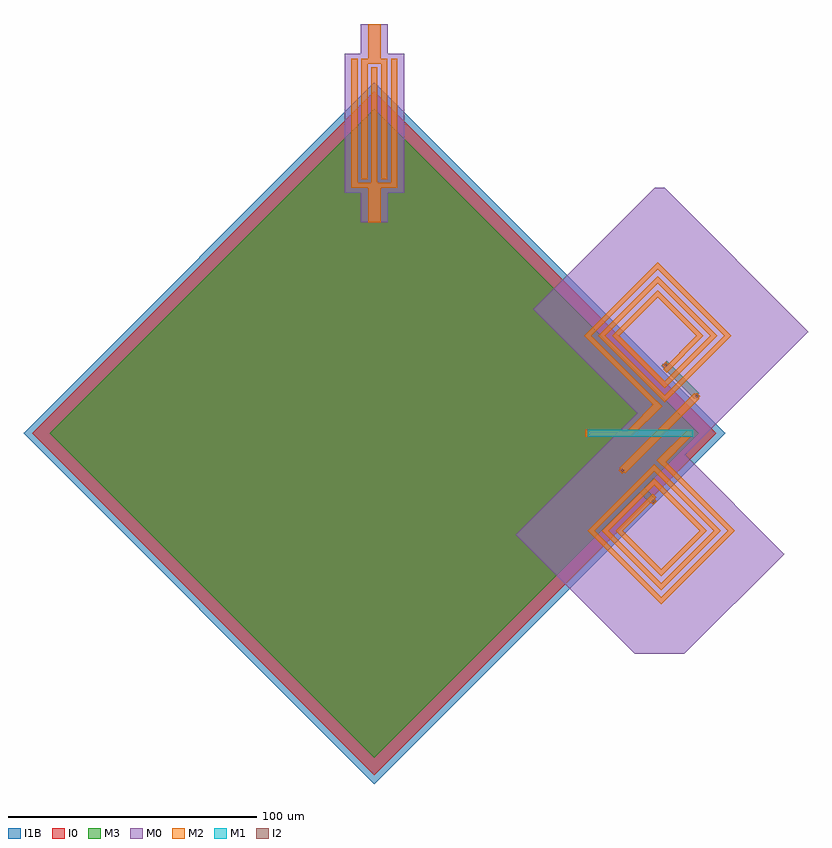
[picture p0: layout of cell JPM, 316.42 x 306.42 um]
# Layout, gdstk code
from math import pi, radians
import gdstk
lib = gdstk.Library(unit=1e-6, precision=1e-09)
def R(c, l, rs):  # rectangles x0, y0, x1, y1
    for r in rs: c.add(gdstk.rectangle(r[:2], r[2:], *l))
def P(c, l, *ps):  # polygons
    for p in ps: c.add(gdstk.Polygon(p, *l))
M1 = (1, 0)
I1B = (3, 0)
M2 = (6, 0)
I2 = (8, 0)
M3 = (10, 0)
M0 = (30, 0)
I0 = (31, 0)

shuntcapacitor = lib.new_cell('ShuntCapacitor')
R(shuntcapacitor, I1B, [(-100,-100,100,100)])
R(shuntcapacitor, M3, [(-92.5,-92.5,92.5,92.5)])
R(shuntcapacitor, I0, [(-97.5,-97.5,97.5,97.5)])

rocap = lib.new_cell('ROCap')
P(rocap, M2, [(-26,-5.25),(-26,-2.5),(-40,-2.5),(-40,2.5),(-26,2.5),(-26,5.25),(22.5,5.25),(22.5,2.75),(-24,2.75),(-24,-2.75),(22.5,-2.75),(22.5,-5.25)],
  [(-26,-9.25),(-26,-6.75),(24,-6.75),(24,-1.25),(-22.5,-1.25),(-22.5,1.25),(24,1.25),(24,6.75),(-26,6.75),(-26,9.25),(26,9.25),(26,2.5),(40,2.5),(40,-2.5),(26,-2.5),(26,-9.25)])
P(rocap, M0, [(-28,-12),(-28,-5.5),(-40,-5.5),(-40,5.5),(-28,5.5),(-28,12),(28,12),(28,5.5),(40,5.5),(40,-5.5),(28,-5.5),(28,-12)])

squarespiral = lib.new_cell('SquareSpiral')
squarespiral.add(gdstk.FlexPath([(-9,12),(11,12),(11,-12),(-13,-12),(-13,16),(15,16),(15,-16),(-17,-16),(-17,20),(19,20),(19,-20),(-21,-20),(-21,21)], 2, ends="flush", simple_path=True, layer=6, datatype=0))  # M2

via_m3_m2_1 = lib.new_cell('Via$M3-M2$1')
R(via_m3_m2_1, M2, [(-1,-1,1,1)])
R(via_m3_m2_1, I2, [(-0.5,-0.5,0.5,0.5)])
R(via_m3_m2_1, M3, [(-1,-1,1,1)])

via_m2_m1_3 = lib.new_cell('Via$M2-M1$3')
R(via_m2_m1_3, M1, [(-1.5,-1.5,1.5,1.5)])
R(via_m2_m1_3, I1B, [(-1,-1,1,1)])
R(via_m2_m1_3, M2, [(-1.5,-1.5,1.5,1.5)])

jpm = lib.new_cell('JPM')
P(jpm, M0, [(47,-89),(-1,-41),(48,8),(6,50),(55,99),(59,99),(117,41),(67.25,-8.75),(107.25,-48.75),(67,-89)])
jpm.add(gdstk.FlexPath([(69,0),(57,-12)], 3, ends="flush", simple_path=True, layer=6, datatype=0))  # M2
jpm.add(gdstk.FlexPath([(57,12),(45,0),(37,0)], 3, ends="flush", simple_path=True, layer=6, datatype=0))  # M2
jpm.add(gdstk.FlexPath([(72,15),(42,-15)], 3, ends="flush", simple_path=True, layer=6, datatype=0))  # M2
jpm.add(gdstk.FlexPath([(27,0),(43,0)], 3, ends="flush", simple_path=True, layer=6, datatype=0))  # M2
jpm.add(gdstk.FlexPath([(68.5,0),(28,0)], 3, ends="flush", simple_path=True, layer=1, datatype=0))  # M1
jpm.add(gdstk.FlexPath([(72,15),(58.75,28.25)], 3, ends="flush", simple_path=True, layer=10, datatype=0))  # M3
jpm.add(gdstk.FlexPath([(42,-15),(54.222,-27.222)], 3, ends="flush", simple_path=True, layer=10, datatype=0))  # M3
jpm.add(gdstk.Reference(shuntcapacitor, (-58,0), rotation=radians(45)))
jpm.add(gdstk.Reference(rocap, (-58,125), rotation=3*pi/2))
jpm.add(gdstk.Reference(squarespiral, (57,-40), rotation=radians(225), x_reflection=True))
jpm.add(gdstk.Reference(squarespiral, (57,40), rotation=radians(45), x_reflection=True))
jpm.add(gdstk.Reference(via_m3_m2_1, (59.5,27.5), rotation=radians(45)))
jpm.add(gdstk.Reference(via_m3_m2_1, (54.5,-27.5), rotation=radians(45)))
jpm.add(gdstk.Reference(via_m3_m2_1, (42,-15), rotation=radians(45)))
jpm.add(gdstk.Reference(via_m3_m2_1, (72,15), rotation=radians(45)))
jpm.add(gdstk.Reference(via_m2_m1_3, (69,0)))

lib.write_gds('JPM.gds')
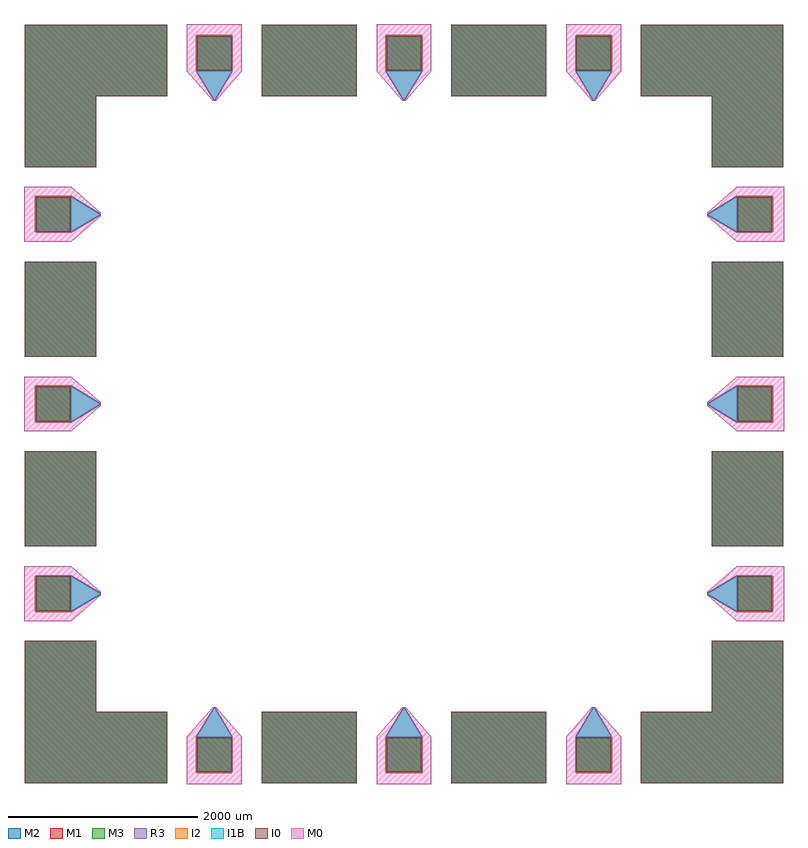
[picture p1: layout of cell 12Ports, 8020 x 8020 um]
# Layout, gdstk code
from math import pi, radians
import gdstk
lib = gdstk.Library(unit=1e-6, precision=1e-09)
def R(c, l, rs):  # rectangles x0, y0, x1, y1
    for r in rs: c.add(gdstk.rectangle(r[:2], r[2:], *l))
def P(c, l, *ps):  # polygons
    for p in ps: c.add(gdstk.Polygon(p, *l))
M1 = (1, 0)
I1B = (3, 0)
M2 = (6, 0)
I2 = (8, 0)
M3 = (10, 0)
R3 = (11, 0)
M0 = (30, 0)
I0 = (31, 0)

rfpad = lib.new_cell('rfPad')
R(rfpad, M1, [(-190,310,190,690)])
R(rfpad, I1B, [(-182.5,317.5,182.5,682.5)])
R(rfpad, M2, [(-190,310,190,690)])
P(rfpad, M2, [(-5,0),(-190,310),(190,310),(5,0)])
R(rfpad, I2, [(-185,315,185,685)])
R(rfpad, M3, [(-190,310,190,690)])
R(rfpad, R3, [(-187.5,312.5,187.5,687.5)])
R(rfpad, M0, [(-290,310,-190,690), (190,310,290,690), (-290,690,290,810)])
P(rfpad, M0, [(-17,0),(-290,310),(-190,310),(-5,0)],
  [(5,0),(190,310),(290,310),(17,0)])
R(rfpad, I0, [(-180,320,180,680)])

cornergroundpad = lib.new_cell('CornerGroundPad')
P(cornergroundpad, M1, [(-750,-750),(-750,750),(750,750),(750,0),(0,0),(0,-750)])
P(cornergroundpad, I1B, [(-750,-750),(-750,750),(750,750),(750,0),(0,0),(0,-750)])
P(cornergroundpad, M2, [(-750,-750),(-750,750),(750,750),(750,0),(0,0),(0,-750)])
P(cornergroundpad, I2, [(-750,-750),(-750,750),(750,750),(750,0),(0,0),(0,-750)])
P(cornergroundpad, M3, [(-750,-750),(-750,750),(750,750),(750,0),(0,0),(0,-750)])
P(cornergroundpad, R3, [(-750,-750),(-750,750),(750,750),(750,0),(0,0),(0,-750)])
P(cornergroundpad, I0, [(-750,-750),(-750,750),(750,750),(750,0),(0,0),(0,-750)])

groundpad = lib.new_cell('GroundPad')
R(groundpad, M1, [(-375,-500,375,500)])
R(groundpad, I1B, [(-375,-500,375,500)])
R(groundpad, M2, [(-375,-500,375,500)])
R(groundpad, I2, [(-375,-500,375,500)])
R(groundpad, M3, [(-375,-500,375,500)])
R(groundpad, R3, [(-375,-500,375,500)])
R(groundpad, I0, [(-375,-500,375,500)])

c_12ports = lib.new_cell('12Ports')
c_12ports.add(gdstk.Reference(rfpad, (-3200,0), rotation=pi/2))
c_12ports.add(gdstk.Reference(rfpad, (-3200,-2000), rotation=pi/2))
c_12ports.add(gdstk.Reference(rfpad, (-2000,-3200), rotation=pi))
c_12ports.add(gdstk.Reference(rfpad, (0,-3200), rotation=pi))
c_12ports.add(gdstk.Reference(rfpad, (2000,-3200), rotation=pi))
c_12ports.add(gdstk.Reference(rfpad, (3200,-2000), rotation=3*pi/2))
c_12ports.add(gdstk.Reference(rfpad, (3200,0), rotation=3*pi/2))
c_12ports.add(gdstk.Reference(rfpad, (3200,2000), rotation=3*pi/2))
c_12ports.add(gdstk.Reference(rfpad, (2000,3200)))
c_12ports.add(gdstk.Reference(rfpad, (-3200,2000), rotation=pi/2))
c_12ports.add(gdstk.Reference(rfpad, (0,3200)))
c_12ports.add(gdstk.Reference(rfpad, (-2000,3200)))
c_12ports.add(gdstk.Reference(cornergroundpad, (-3250,3250)))
c_12ports.add(gdstk.Reference(cornergroundpad, (3250,3250), rotation=3*pi/2))
c_12ports.add(gdstk.Reference(cornergroundpad, (-3250,-3250), rotation=pi/2))
c_12ports.add(gdstk.Reference(cornergroundpad, (3250,-3250), rotation=pi))
c_12ports.add(gdstk.Reference(groundpad, (-3625,1000)))
c_12ports.add(gdstk.Reference(groundpad, (-3625,-1000), rotation=pi))
c_12ports.add(gdstk.Reference(groundpad, (3625,1000), rotation=pi))
c_12ports.add(gdstk.Reference(groundpad, (3625,-1000), rotation=pi))
c_12ports.add(gdstk.Reference(groundpad, (-1000,-3625), rotation=3*pi/2))
c_12ports.add(gdstk.Reference(groundpad, (1000,-3625), rotation=3*pi/2))
c_12ports.add(gdstk.Reference(groundpad, (-1000,3625), rotation=3*pi/2))
c_12ports.add(gdstk.Reference(groundpad, (1000,3625), rotation=3*pi/2))

lib.write_gds('12Ports.gds')
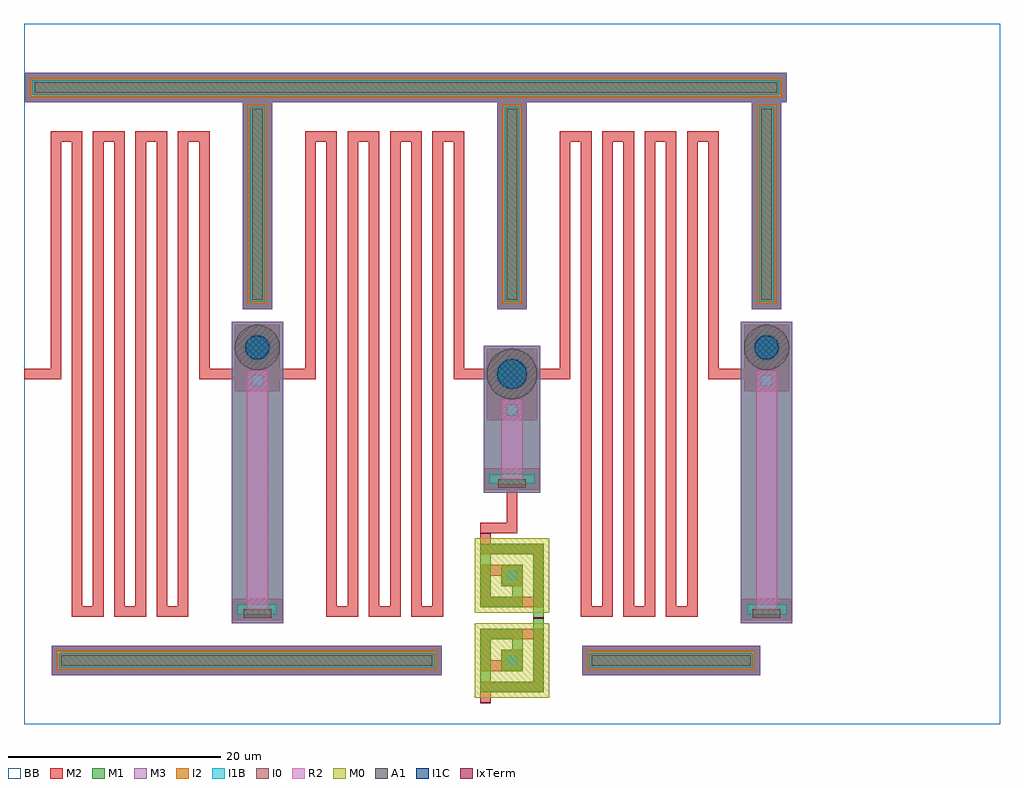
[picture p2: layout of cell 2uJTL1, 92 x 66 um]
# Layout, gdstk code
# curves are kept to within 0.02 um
from math import pi, radians
import gdstk
lib = gdstk.Library(unit=1e-6, precision=1e-09)
def R(c, l, rs):  # rectangles x0, y0, x1, y1
    for r in rs: c.add(gdstk.rectangle(r[:2], r[2:], *l))
def P(c, l, *ps):  # polygons
    for p in ps: c.add(gdstk.Polygon(p, *l))
M1 = (1, 0)
BB = (1, 3)
I1B = (3, 0)
I1C = (4, 0)
A1 = (5, 0)
M2 = (6, 0)
I2 = (8, 0)
R2 = (9, 0)
M3 = (10, 0)
M0 = (30, 0)
I0 = (31, 0)
IxTerm = (63, 0)

via_m3_m0_9 = lib.new_cell('Via$M3-M0$9')
via_m3_m0_9.add(gdstk.FlexPath([(-9.2,0),(9.2,0)], 1.399, ends="flush", simple_path=True, layer=3, datatype=0))  # I1B
via_m3_m0_9.add(gdstk.FlexPath([(-9.899,0),(9.899,0)], 2.799, ends="flush", simple_path=True, layer=6, datatype=0))  # M2
via_m3_m0_9.add(gdstk.FlexPath([(-9.899,0),(9.899,0)], 2.799, ends="flush", simple_path=True, layer=1, datatype=0))  # M1
via_m3_m0_9.add(gdstk.FlexPath([(-9.899,0),(9.899,0)], 2.799, ends="flush", simple_path=True, layer=10, datatype=0))  # M3
via_m3_m0_9.add(gdstk.FlexPath([(-9.399,0),(9.399,0)], 1.8, ends="flush", simple_path=True, layer=8, datatype=0))  # I2
via_m3_m0_9.add(gdstk.FlexPath([(-9,0),(9,0)], 1, ends="flush", simple_path=True, layer=31, datatype=0))  # I0

jj_64 = lib.new_cell('JJ$64')
R(jj_64, M1, [(-2.429,-25.993,2.429,2.429)])
R(jj_64, I1B, [(-1.879,-25.193,1.879,-24.193), (-0.5,-3.63,0.5,-2.63)])
P(jj_64, I1B, [(0,-1.185),(-0.231,-1.162),(-0.453,-1.095),(-0.658,-0.985),(-0.838,-0.838),(-0.985,-0.658),(-1.095,-0.453),(-1.162,-0.231),(-1.185,0),(-1.162,0.231),(-1.095,0.453),(-0.985,0.658),(-0.838,0.838),(-0.658,0.985),(-0.453,1.095),(-0.231,1.162),(0,1.185),(0.231,1.162),(0.453,1.095),(0.658,0.985),(0.838,0.838),(0.985,0.658),(1.095,0.453),(1.162,0.231),(1.185,0),(1.162,-0.231),(1.095,-0.453),(0.985,-0.658),(0.838,-0.838),(0.658,-0.985),(0.453,-1.095),(0.231,-1.162)])
P(jj_64, I1C, [(0,-1.128),(-0.22,-1.107),(-0.432,-1.042),(-0.627,-0.938),(-0.798,-0.798),(-0.938,-0.627),(-1.042,-0.432),(-1.107,-0.22),(-1.128,0),(-1.107,0.22),(-1.042,0.432),(-0.938,0.627),(-0.798,0.798),(-0.627,0.938),(-0.432,1.042),(-0.22,1.107),(0,1.128),(0.22,1.107),(0.432,1.042),(0.627,0.938),(0.798,0.798),(0.938,0.627),(1.042,0.432),(1.107,0.22),(1.128,0),(1.107,-0.22),(1.042,-0.432),(0.938,-0.627),(0.798,-0.798),(0.627,-0.938),(0.432,-1.042),(0.22,-1.107)])
P(jj_64, A1, [(0,-2.13),(-0.416,-2.089),(-0.815,-1.968),(-1.183,-1.771),(-1.506,-1.506),(-1.771,-1.183),(-1.968,-0.815),(-2.089,-0.416),(-2.13,0),(-2.089,0.416),(-1.968,0.815),(-1.771,1.183),(-1.506,1.506),(-1.183,1.771),(-0.815,1.968),(-0.416,2.089),(0,2.13),(0.416,2.089),(0.815,1.968),(1.183,1.771),(1.506,1.506),(1.771,1.183),(1.968,0.815),(2.089,0.416),(2.13,0),(2.089,-0.416),(1.968,-0.815),(1.771,-1.183),(1.506,-1.506),(1.183,-1.771),(0.815,-1.968),(0.416,-2.089)])
R(jj_64, M2, [(-2.38,-25.693,2.38,-23.693), (-2.13,-4.13,2.13,-2.13), (-2.13,-2.13,2.13,2.13)])
R(jj_64, I2, [(-1.879,-25.193,1.879,-24.193)])
R(jj_64, M3, [(-2.429,-25.993,2.429,2.429), (-2.38,-25.693,2.38,-23.693)])
R(jj_64, I0, [(-1.3,-25.493,1.3,-24.693)])
jj_64.add(gdstk.FlexPath([(0,-2.13),(0,-24.693)], 2, ends="flush", simple_path=True, layer=9, datatype=0))  # R2

jj_69 = lib.new_cell('JJ$69')
R(jj_69, M1, [(-2.679,-11.201,2.679,2.679)])
R(jj_69, I1B, [(-2.13,-10.401,2.13,-9.401), (-0.5,-3.88,0.5,-2.88)])
P(jj_69, I1B, [(0,-1.451),(-0.283,-1.423),(-0.555,-1.341),(-0.806,-1.207),(-1.026,-1.026),(-1.207,-0.806),(-1.341,-0.555),(-1.423,-0.283),(-1.451,0),(-1.423,0.283),(-1.341,0.555),(-1.207,0.806),(-1.026,1.026),(-0.806,1.207),(-0.555,1.341),(-0.283,1.423),(0,1.451),(0.283,1.423),(0.555,1.341),(0.806,1.207),(1.026,1.026),(1.207,0.806),(1.341,0.555),(1.423,0.283),(1.451,0),(1.423,-0.283),(1.341,-0.555),(1.207,-0.806),(1.026,-1.026),(0.806,-1.207),(0.555,-1.341),(0.283,-1.423)])
P(jj_69, I1C, [(0,-1.382),(-0.27,-1.355),(-0.529,-1.277),(-0.768,-1.149),(-0.977,-0.977),(-1.149,-0.768),(-1.277,-0.529),(-1.355,-0.27),(-1.382,0),(-1.355,0.27),(-1.277,0.529),(-1.149,0.768),(-0.977,0.977),(-0.768,1.149),(-0.529,1.277),(-0.27,1.355),(0,1.382),(0.27,1.355),(0.529,1.277),(0.768,1.149),(0.977,0.977),(1.149,0.768),(1.277,0.529),(1.355,0.27),(1.382,0),(1.355,-0.27),(1.277,-0.529),(1.149,-0.768),(0.977,-0.977),(0.768,-1.149),(0.529,-1.277),(0.27,-1.355)])
P(jj_69, A1, [(0,-2.38),(-0.464,-2.334),(-0.911,-2.199),(-1.322,-1.979),(-1.683,-1.683),(-1.979,-1.322),(-2.199,-0.911),(-2.334,-0.464),(-2.38,0),(-2.334,0.464),(-2.199,0.911),(-1.979,1.322),(-1.683,1.683),(-1.322,1.979),(-0.911,2.199),(-0.464,2.334),(0,2.38),(0.464,2.334),(0.911,2.199),(1.322,1.979),(1.683,1.683),(1.979,1.322),(2.199,0.911),(2.334,0.464),(2.38,0),(2.334,-0.464),(2.199,-0.911),(1.979,-1.322),(1.683,-1.683),(1.322,-1.979),(0.911,-2.199),(0.464,-2.334)])
R(jj_69, M2, [(-2.63,-10.901,2.63,-8.901), (-2.38,-4.38,2.38,-2.38), (-2.38,-2.38,2.38,2.38)])
R(jj_69, I2, [(-2.13,-10.401,2.13,-9.401)])
R(jj_69, M3, [(-2.679,-11.201,2.679,2.679), (-2.63,-10.901,2.63,-8.901)])
R(jj_69, I0, [(-1.3,-10.701,1.3,-9.901)])
jj_69.add(gdstk.FlexPath([(0,-2.38),(0,-9.901)], 2, ends="flush", simple_path=True, layer=9, datatype=0))  # R2

meanderinductor_51 = lib.new_cell('MeanderInductor$51')
meanderinductor_51.add(gdstk.FlexPath([(-10,0),(-7,0),(-7,22.387),(-5,22.387),(-5,-22.387),(-3,-22.387),(-3,22.387),(-1,22.387),(-1,-22.387),(1,-22.387),(1,22.387),(3,22.387),(3,-22.387),(5,-22.387),(5,22.387),(7,22.387),(7,0),(10,0)], 1, ends="flush", simple_path=True, layer=6, datatype=0))  # M2

ak6vm21 = lib.new_cell('AK6VM21')
R(ak6vm21, M1, [(-1,-1,1,1)])
R(ak6vm21, I1B, [(-0.5,-0.5,0.5,0.5)])
R(ak6vm21, M2, [(-1,-1,1,1)])

ak6mon103 = lib.new_cell('AK6MON103')
R(ak6mon103, M0, [(-6,0.5,1,7.5)])
ak6mon103.add(gdstk.FlexPath([(0,0),(0,1.5),(-5,1.5),(-5,6.5),(0,6.5),(0,3.5),(-1,3.5),(-1.5,3.5)], 1, ends="flush", simple_path=True, layer=6, datatype=0))  # M2
ak6mon103.add(gdstk.FlexPath([(-3,5),(-3,6.5),(0,6.5),(0,1.5),(-5,1.5),(-5,8)], 1, ends="flush", simple_path=True, layer=1, datatype=0))  # M1
ak6mon103.add(gdstk.FlexPath([(-0.5,0),(0.5,0)], 0.1, ends="flush", simple_path=True, layer=63, datatype=0))  # IxTerm
ak6mon103.add(gdstk.FlexPath([(-5.5,8),(-4.5,8)], 0.1, ends="flush", simple_path=True, layer=63, datatype=0))  # IxTerm
ak6mon103.add(gdstk.Reference(ak6vm21, (-2.5,4)))
ak6mon103.add(gdstk.Label('P1+ M2', (0,0), layer=64, texttype=0))
ak6mon103.add(gdstk.Label('P1- M1', (-5,8), layer=64, texttype=0))

via_m3_m0_10 = lib.new_cell('Via$M3-M0$10')
via_m3_m0_10.add(gdstk.FlexPath([(-7.7,0),(7.7,0)], 1.399, ends="flush", simple_path=True, layer=3, datatype=0))  # I1B
via_m3_m0_10.add(gdstk.FlexPath([(-8.4,0),(8.4,0)], 2.799, ends="flush", simple_path=True, layer=6, datatype=0))  # M2
via_m3_m0_10.add(gdstk.FlexPath([(-8.4,0),(8.4,0)], 2.799, ends="flush", simple_path=True, layer=1, datatype=0))  # M1
via_m3_m0_10.add(gdstk.FlexPath([(-8.4,0),(8.4,0)], 2.799, ends="flush", simple_path=True, layer=10, datatype=0))  # M3
via_m3_m0_10.add(gdstk.FlexPath([(-7.9,0),(7.9,0)], 1.8, ends="flush", simple_path=True, layer=8, datatype=0))  # I2
via_m3_m0_10.add(gdstk.FlexPath([(-7.5,0),(7.5,0)], 1, ends="flush", simple_path=True, layer=31, datatype=0))  # I0

via_m3_m0_7 = lib.new_cell('Via$M3-M0$7')
via_m3_m0_7.add(gdstk.FlexPath([(-17.7,0),(17.7,0)], 1.399, ends="flush", simple_path=True, layer=3, datatype=0))  # I1B
via_m3_m0_7.add(gdstk.FlexPath([(-18.4,0),(18.4,0)], 2.799, ends="flush", simple_path=True, layer=6, datatype=0))  # M2
via_m3_m0_7.add(gdstk.FlexPath([(-18.4,0),(18.4,0)], 2.799, ends="flush", simple_path=True, layer=1, datatype=0))  # M1
via_m3_m0_7.add(gdstk.FlexPath([(-18.4,0),(18.4,0)], 2.799, ends="flush", simple_path=True, layer=10, datatype=0))  # M3
via_m3_m0_7.add(gdstk.FlexPath([(-17.9,0),(17.9,0)], 1.8, ends="flush", simple_path=True, layer=8, datatype=0))  # I2
via_m3_m0_7.add(gdstk.FlexPath([(-17.5,0),(17.5,0)], 1, ends="flush", simple_path=True, layer=31, datatype=0))  # I0

via_m3_m0_13 = lib.new_cell('Via$M3-M0$13')
via_m3_m0_13.add(gdstk.FlexPath([(-35.2,0),(35.2,0)], 1.399, ends="flush", simple_path=True, layer=3, datatype=0))  # I1B
via_m3_m0_13.add(gdstk.FlexPath([(-35.9,0),(35.9,0)], 2.799, ends="flush", simple_path=True, layer=6, datatype=0))  # M2
via_m3_m0_13.add(gdstk.FlexPath([(-35.9,0),(35.9,0)], 2.799, ends="flush", simple_path=True, layer=1, datatype=0))  # M1
via_m3_m0_13.add(gdstk.FlexPath([(-35.9,0),(35.9,0)], 2.799, ends="flush", simple_path=True, layer=10, datatype=0))  # M3
via_m3_m0_13.add(gdstk.FlexPath([(-35.4,0),(35.4,0)], 1.8, ends="flush", simple_path=True, layer=8, datatype=0))  # I2
via_m3_m0_13.add(gdstk.FlexPath([(-35,0),(35,0)], 1, ends="flush", simple_path=True, layer=31, datatype=0))  # I0

jj_66 = lib.new_cell('JJ$66')
R(jj_66, M1, [(-2.429,-25.993,2.429,2.429)])
R(jj_66, I1B, [(-1.879,-25.193,1.879,-24.193), (-0.5,-3.63,0.5,-2.63)])
P(jj_66, I1B, [(0,-1.185),(-0.231,-1.162),(-0.453,-1.095),(-0.658,-0.985),(-0.838,-0.838),(-0.985,-0.658),(-1.095,-0.453),(-1.162,-0.231),(-1.185,0),(-1.162,0.231),(-1.095,0.453),(-0.985,0.658),(-0.838,0.838),(-0.658,0.985),(-0.453,1.095),(-0.231,1.162),(0,1.185),(0.231,1.162),(0.453,1.095),(0.658,0.985),(0.838,0.838),(0.985,0.658),(1.095,0.453),(1.162,0.231),(1.185,0),(1.162,-0.231),(1.095,-0.453),(0.985,-0.658),(0.838,-0.838),(0.658,-0.985),(0.453,-1.095),(0.231,-1.162)])
P(jj_66, I1C, [(0,-1.128),(-0.22,-1.107),(-0.432,-1.042),(-0.627,-0.938),(-0.798,-0.798),(-0.938,-0.627),(-1.042,-0.432),(-1.107,-0.22),(-1.128,0),(-1.107,0.22),(-1.042,0.432),(-0.938,0.627),(-0.798,0.798),(-0.627,0.938),(-0.432,1.042),(-0.22,1.107),(0,1.128),(0.22,1.107),(0.432,1.042),(0.627,0.938),(0.798,0.798),(0.938,0.627),(1.042,0.432),(1.107,0.22),(1.128,0),(1.107,-0.22),(1.042,-0.432),(0.938,-0.627),(0.798,-0.798),(0.627,-0.938),(0.432,-1.042),(0.22,-1.107)])
P(jj_66, A1, [(0,-2.13),(-0.416,-2.089),(-0.815,-1.968),(-1.183,-1.771),(-1.506,-1.506),(-1.771,-1.183),(-1.968,-0.815),(-2.089,-0.416),(-2.13,0),(-2.089,0.416),(-1.968,0.815),(-1.771,1.183),(-1.506,1.506),(-1.183,1.771),(-0.815,1.968),(-0.416,2.089),(0,2.13),(0.416,2.089),(0.815,1.968),(1.183,1.771),(1.506,1.506),(1.771,1.183),(1.968,0.815),(2.089,0.416),(2.13,0),(2.089,-0.416),(1.968,-0.815),(1.771,-1.183),(1.506,-1.506),(1.183,-1.771),(0.815,-1.968),(0.416,-2.089)])
R(jj_66, M2, [(-2.38,-25.693,2.38,-23.693), (-2.13,-4.13,2.13,-2.13), (-2.13,-2.13,2.13,2.13)])
R(jj_66, I2, [(-1.879,-25.193,1.879,-24.193)])
R(jj_66, M3, [(-2.429,-25.993,2.429,2.429), (-2.38,-25.693,2.38,-23.693)])
R(jj_66, I0, [(-1.3,-25.493,1.3,-24.693)])
jj_66.add(gdstk.FlexPath([(0,-2.13),(0,-24.693)], 2, ends="flush", simple_path=True, layer=9, datatype=0))  # R2

c_2ujtl1 = lib.new_cell('2uJTL1')
R(c_2ujtl1, BB, [(-46,-33,46,33)])
c_2ujtl1.add(gdstk.FlexPath([(0,-9.5),(0,-14.5),(-3,-14.5)], 1, ends="flush", simple_path=True, layer=6, datatype=0))  # M2
c_2ujtl1.add(gdstk.Reference(via_m3_m0_9, (-24,16), rotation=pi/2))
c_2ujtl1.add(gdstk.Reference(jj_64, (24,2.5)))
c_2ujtl1.add(gdstk.Reference(jj_69, (0,0)))
r = gdstk.Reference(meanderinductor_51, (-36,0)); r.repetition = gdstk.Repetition(3, 1, v1=(24,0), v2=(0,0)); c_2ujtl1.add(r)
c_2ujtl1.add(gdstk.Reference(ak6mon103, (-2.5,-15), rotation=pi))
c_2ujtl1.add(gdstk.Reference(ak6mon103, (-2.5,-31), rotation=pi, x_reflection=True))
c_2ujtl1.add(gdstk.Reference(via_m3_m0_10, (15,-27)))
c_2ujtl1.add(gdstk.Reference(via_m3_m0_7, (-25,-27)))
c_2ujtl1.add(gdstk.Reference(via_m3_m0_13, (-10,27)))
c_2ujtl1.add(gdstk.Reference(via_m3_m0_9, (0,16), rotation=pi/2))
c_2ujtl1.add(gdstk.Reference(via_m3_m0_9, (24,16), rotation=pi/2))
c_2ujtl1.add(gdstk.Reference(jj_66, (-24,2.5)))

lib.write_gds('2uJTL1.gds')
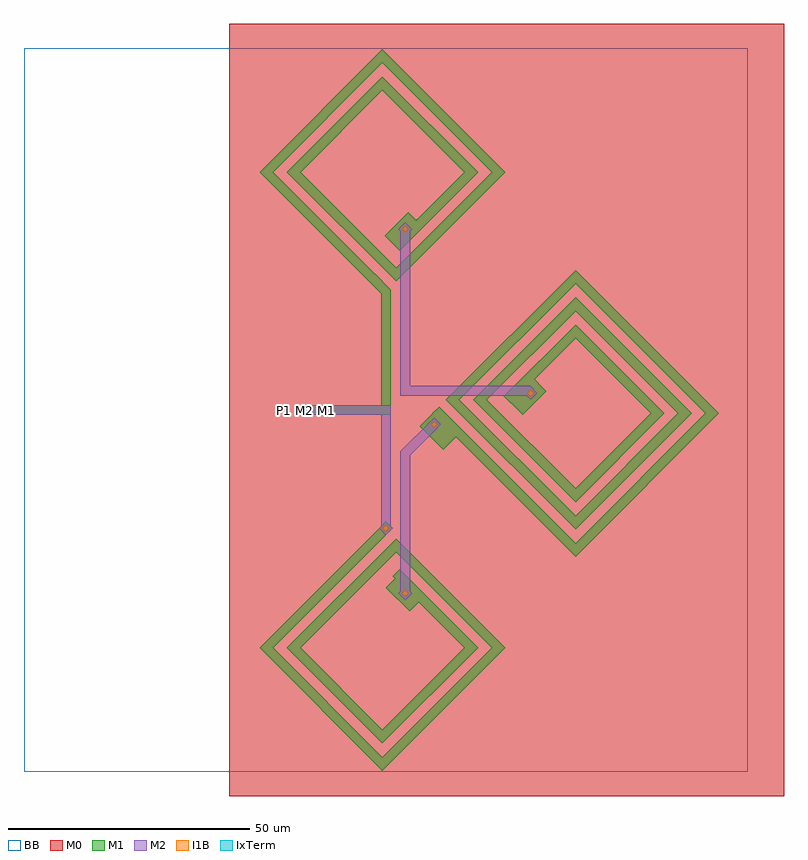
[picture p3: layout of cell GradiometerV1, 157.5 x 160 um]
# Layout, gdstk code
from math import pi, radians
import gdstk
lib = gdstk.Library(unit=1e-6, precision=1e-09)
def R(c, l, rs):  # rectangles x0, y0, x1, y1
    for r in rs: c.add(gdstk.rectangle(r[:2], r[2:], *l))
def P(c, l, *ps):  # polygons
    for p in ps: c.add(gdstk.Polygon(p, *l))
M1 = (1, 0)
BB = (1, 3)
I1B = (3, 0)
M2 = (6, 0)
M0 = (30, 0)
IxTerm = (63, 0)

squarespiral_2 = lib.new_cell('SquareSpiral$2')
squarespiral_2.add(gdstk.FlexPath([(-10,13),(12,13),(12,-13),(-14,-13),(-14,17),(16,17),(16,-17),(-18,-17),(-18,18)], 2, ends="flush", simple_path=True, layer=1, datatype=0))  # M1

squarespiral_4 = lib.new_cell('SquareSpiral$4')
squarespiral_4.add(gdstk.FlexPath([(-10,13),(12,13),(12,-13),(-14,-13),(-14,17),(16,17),(16,-17),(-18,-17),(-18,18)], 2, ends="flush", simple_path=True, layer=1, datatype=0))  # M1

squarespiral_9 = lib.new_cell('SquareSpiral$9')
squarespiral_9.add(gdstk.FlexPath([(-9,12),(11,12),(11,-12),(-13,-12),(-13,16),(15,16),(15,-16),(-17,-16),(-17,20),(19,20),(19,-20),(-21,-20),(-21,21)], 2, ends="flush", simple_path=True, layer=1, datatype=0))  # M1

via_m2_m1 = lib.new_cell('Via$M2-M1')
R(via_m2_m1, M1, [(-1,-1,1,1)])
R(via_m2_m1, I1B, [(-0.5,-0.5,0.5,0.5)])
R(via_m2_m1, M2, [(-1,-1,1,1)])

gradiometerv1 = lib.new_cell('GradiometerV1')
P(gradiometerv1, M1, [(2.823,33.013),(-0.237,36.073),(4.677,40.987),(7.737,37.927)],
  [(28.323,-0.987),(25.263,2.073),(30.177,6.987),(33.237,3.927)],
  [(11.927,-8.237),(7.013,-3.323),(10.073,-0.263),(14.987,-5.177)],
  [(4.927,-41.737),(0.013,-36.823),(3.073,-33.763),(7.987,-38.677)])
R(gradiometerv1, BB, [(-75,-75,75,75)])
R(gradiometerv1, M0, [(-32.5,-80,82.5,80)])
R(gradiometerv1, IxTerm, [(-17,-1,-16,1)])
gradiometerv1.add(gdstk.FlexPath([(4,37.5),(4,4),(30,4)], 2, ends="flush", simple_path=True, layer=6, datatype=0))  # M2
gradiometerv1.add(gdstk.FlexPath([(4,-38),(4,-9),(10,-3)], 2, ends="flush", simple_path=True, layer=6, datatype=0))  # M2
gradiometerv1.add(gdstk.FlexPath([(0,-24.544),(0,0),(-16.5,0)], 2, ends="flush", simple_path=True, layer=6, datatype=0))  # M2
gradiometerv1.add(gdstk.FlexPath([(-2.956,27.5),(0,24.544),(0,0),(-16.5,0)], 2, ends="flush", simple_path=True, layer=1, datatype=0))  # M1
gradiometerv1.add(gdstk.Reference(squarespiral_2, (0,50), rotation=radians(45), x_reflection=True))
gradiometerv1.add(gdstk.Reference(squarespiral_4, (0,-50), rotation=radians(315)))
gradiometerv1.add(gdstk.Reference(squarespiral_9, (40,0), rotation=radians(45)))
gradiometerv1.add(gdstk.Reference(via_m2_m1, (10,-3), rotation=radians(45)))
gradiometerv1.add(gdstk.Reference(via_m2_m1, (30,3.5), rotation=radians(45)))
gradiometerv1.add(gdstk.Reference(via_m2_m1, (0,-24.5), rotation=radians(45)))
gradiometerv1.add(gdstk.Reference(via_m2_m1, (4,37.5), rotation=radians(45)))
gradiometerv1.add(gdstk.Reference(via_m2_m1, (4,-38), rotation=radians(45)))
gradiometerv1.add(gdstk.Label('P1 M2 M1', (-16.5,0), layer=64, texttype=0))

lib.write_gds('GradiometerV1.gds')
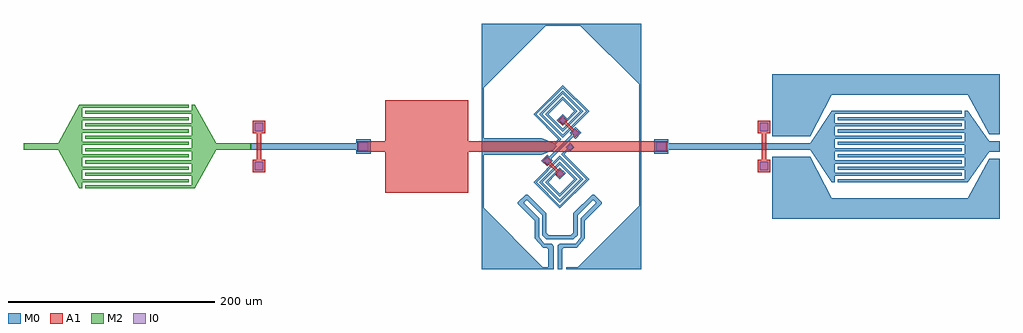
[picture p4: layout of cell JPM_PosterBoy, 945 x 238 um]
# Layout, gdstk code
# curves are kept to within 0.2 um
import gdstk
lib = gdstk.Library(unit=1e-6, precision=1e-09)
def R(c, l, rs):  # rectangles x0, y0, x1, y1
    for r in rs: c.add(gdstk.rectangle(r[:2], r[2:], *l))
def P(c, l, *ps):  # polygons
    for p in ps: c.add(gdstk.Polygon(p, *l))
A1 = (5, 0)
M2 = (6, 0)
M0 = (30, 0)
I0 = (31, 0)

c_jpm_proxy = lib.new_cell('C_JPM_Proxy')
P(c_jpm_proxy, A1, [(5,-45),(5,-5),(0,-5),(0,5),(5,5),(5,45),(85,45),(85,5),(90,5),(90,-5),(85,-5),(85,-45)])

c_c_proxy = lib.new_cell('C_C_Proxy')
P(c_c_proxy, M0, [(0,-70),(0,-10),(37,-10),(57.5,-50),(189.5,-50),(210,-12),(220,-12),(220,-70)],
  [(63.5,-34.5),(63.5,-31.5),(186.5,-31.5),(186.5,-22.5),(63.5,-22.5),(63.5,-19.5),(186.5,-19.5),(186.5,-10.5),(63.5,-10.5),(63.5,-7.5),(186.5,-7.5),(186.5,1.5),(63.5,1.5),(63.5,4.5),(186.5,4.5),(186.5,13.5),(63.5,13.5),(63.5,16.5),(186.5,16.5),(186.5,25.5),(63.5,25.5),(63.5,28.5),(186.5,28.5),(186.5,34.5),(189.5,34.5),(210,5),(220,5),(220,-5),(210,-5),(189.5,-34.5)],
  [(0,10),(0,70),(220,70),(220,12),(210,12),(189.5,50),(57.5,50),(37,10)],
  [(57.5,-34.5),(37,-3),(0,-3),(0,3),(37,3),(57.5,34.5),(183.5,34.5),(183.5,31.5),(60.5,31.5),(60.5,22.5),(183.5,22.5),(183.5,19.5),(60.5,19.5),(60.5,10.5),(183.5,10.5),(183.5,7.5),(60.5,7.5),(60.5,-1.5),(183.5,-1.5),(183.5,-4.5),(60.5,-4.5),(60.5,-13.5),(183.5,-13.5),(183.5,-16.5),(60.5,-16.5),(60.5,-25.5),(183.5,-25.5),(183.5,-28.5),(60.5,-28.5),(60.5,-34.5)])

c_ro_proxy = lib.new_cell('C_RO_Proxy')
P(c_ro_proxy, M2, [(60,-40.5),(60,-37.5),(163,-37.5),(163,-28.5),(60,-28.5),(60,-25.5),(163,-25.5),(163,-16.5),(60,-16.5),(60,-13.5),(163,-13.5),(163,-4.5),(60,-4.5),(60,-1.5),(163,-1.5),(163,7.5),(60,7.5),(60,10.5),(163,10.5),(163,19.5),(60,19.5),(60,22.5),(163,22.5),(163,31.5),(60,31.5),(60,34.5),(163,34.5),(163,40.5),(166,40.5),(186.5,3),(220,3),(220,-3),(186.5,-3),(166,-40.5)],
  [(54,-40.5),(33.5,-3),(0,-3),(0,3),(33.5,3),(54,40.5),(160,40.5),(160,37.5),(57,37.5),(57,28.5),(160,28.5),(160,25.5),(57,25.5),(57,16.5),(160,16.5),(160,13.5),(57,13.5),(57,4.5),(160,4.5),(160,1.5),(57,1.5),(57,-7.5),(160,-7.5),(160,-10.5),(57,-10.5),(57,-19.5),(160,-19.5),(160,-22.5),(57,-22.5),(57,-31.5),(160,-31.5),(160,-34.5),(57,-34.5),(57,-40.5)])

jpminductorproxy = lib.new_cell('JPMInductorProxy')
P(jpminductorproxy, M0, [(0,-119),(0,119),(154.5,119),(154.5,-119),(82,-119),(82,-117),(93,-117),(152.5,-57.5),(152.5,60.25),(95.75,117),(62,117),(2,57),(2,8),(58.5,8),(68.439,4.053),(68.764,4.346),(70.162,2.948),(74.349,7.135),(50.308,31.176),(78.592,59.46),(104.048,34.004),(78.592,8.548),(55.964,31.176),(78.592,53.804),(98.391,34.005),(78.591,14.205),(61.621,31.175),(78.592,48.146),(92.734,34.004),(78.592,19.862),(72.935,25.519),(78.592,31.176),(82.835,26.933),(89.906,34.004),(78.592,45.318),(64.45,31.176),(78.591,17.035),(95.562,34.006),(78.592,50.976),(58.792,31.176),(78.591,11.377),(101.219,34.005),(78.592,56.632),(53.136,31.176),(77.178,7.134),(71.577,1.533),(73.007,0.103),(69,-4),(58.5,-8),(2,-8),(2,-59.5),(59.254,-117),(64.625,-117),(64.625,-99.625),(63,-98),(59.75,-98),(51.75,-89),(51.75,-72),(35.25,-55.5),(35.25,-54),(42.75,-46.5),(44.75,-46.5),(62.75,-64.5),(62.75,-83.5),(65.25,-86),(86.5,-86),(89,-83.5),(89,-64.5),(107,-46.5),(109,-46.5),(116.5,-54),(116.5,-55.5),(100,-72),(100,-89),(92,-98),(79.5,-98),(78,-99.5),(78,-119),(74,-119),(74,-95.5),(75.5,-94),(91,-94),(96,-88),(96,-69.5),(110.5,-55),(110.5,-54),(108.5,-52),(107.5,-52),(93,-66.5),(93,-86),(89,-90),(62.75,-90),(58.75,-86),(58.75,-66.5),(44.25,-52),(43.25,-52),(41.25,-54),(41.25,-55),(55.75,-69.5),(55.75,-88),(60.75,-94),(68,-94),(70,-96.5),(70,-119)],
  [(75.834,-59.994),(50.378,-34.538),(75.834,-9.082),(98.462,-31.71),(75.834,-54.338),(56.035,-34.539),(75.835,-14.739),(92.805,-31.709),(75.834,-48.68),(61.692,-34.538),(75.834,-20.396),(81.491,-26.053),(75.834,-31.71),(71.591,-27.467),(64.52,-34.538),(75.834,-45.852),(89.976,-31.71),(75.835,-17.569),(58.864,-34.54),(75.834,-51.51),(95.634,-31.71),(75.835,-11.911),(53.207,-34.539),(75.834,-57.166),(101.29,-31.71),(77.248,-7.668),(82.905,-2.011),(81.491,-0.597),(85.733,3.645),(89.976,-0.598),(85.734,-4.84),(84.32,-3.426),(80.077,-7.669),(104.118,-31.71)],
  [(63.461,-19.342),(57.803,-13.679),(63.46,-8.022),(65.569,-10.131),(87.077,11.377),(85.309,13.145),(91.039,18.842),(96.696,13.185),(90.966,7.488),(88.861,9.593),(67.353,-11.915),(69.118,-13.685)])

jpm_posterboy = lib.new_cell('JPM_PosterBoy')
R(jpm_posterboy, A1, [(323,-5,623.5,5)])
P(jpm_posterboy, A1, [(519.326,-30.39),(515.084,-26.148),(519.327,-21.905),(523.569,-26.147)],
  [(516.145,-25.087),(508.013,-16.955),(510.134,-14.834),(518.266,-22.966)],
  [(506.952,-18.016),(502.709,-13.773),(506.952,-9.53),(511.195,-13.773)],
  [(534.428,8.909),(530.185,13.152),(534.428,17.395),(538.671,13.152)],
  [(531.246,14.213),(523.114,22.345),(525.235,24.466),(533.367,16.334)],
  [(522.054,21.284),(517.811,25.527),(522.053,29.769),(526.296,25.526)],
  [(711,-25),(711,-13),(715,-13),(715,13),(711,13),(711,25),(723,25),(723,13),(719,13),(719,-13),(723,-13),(723,-25)],
  [(222,-25),(222,-13),(226,-13),(226,13),(222,13),(222,25),(234,25),(234,13),(230,13),(230,-13),(234,-13),(234,-25)])
P(jpm_posterboy, M0, [(322,-7),(322,-3),(220,-3),(220,3),(322,3),(322,7),(336,7),(336,-7)],
  [(610.5,-7),(610.5,7),(624.5,7),(624.5,3),(727,3),(727,-3),(624.5,-3),(624.5,-7)])
R(jpm_posterboy, I0, [(224,-23,232,-15), (713,-23,721,-15), (324,-4,334,4), (612.5,-4,622.5,4), (224,15,232,23), (713,15,721,23)])
P(jpm_posterboy, I0, [(519.326,-29.683),(515.791,-26.148),(519.327,-22.612),(522.862,-26.147)],
  [(506.953,-17.309),(503.417,-13.773),(506.952,-10.238),(510.488,-13.774)],
  [(534.427,9.617),(530.892,13.152),(534.428,16.688),(537.963,13.153)],
  [(522.054,21.991),(518.518,25.527),(522.053,29.062),(525.589,25.526)],
  [(529.262,-3.633),(526.261,-0.632),(529.262,2.369),(532.263,-0.632)])
jpm_posterboy.add(gdstk.Reference(c_jpm_proxy, (345.5,0)))
jpm_posterboy.add(gdstk.Reference(c_c_proxy, (725,0)))
jpm_posterboy.add(gdstk.Reference(c_ro_proxy, (0,0)))
jpm_posterboy.add(gdstk.Reference(jpminductorproxy, (443.501,0)))

lib.write_gds('JPM_PosterBoy.gds')
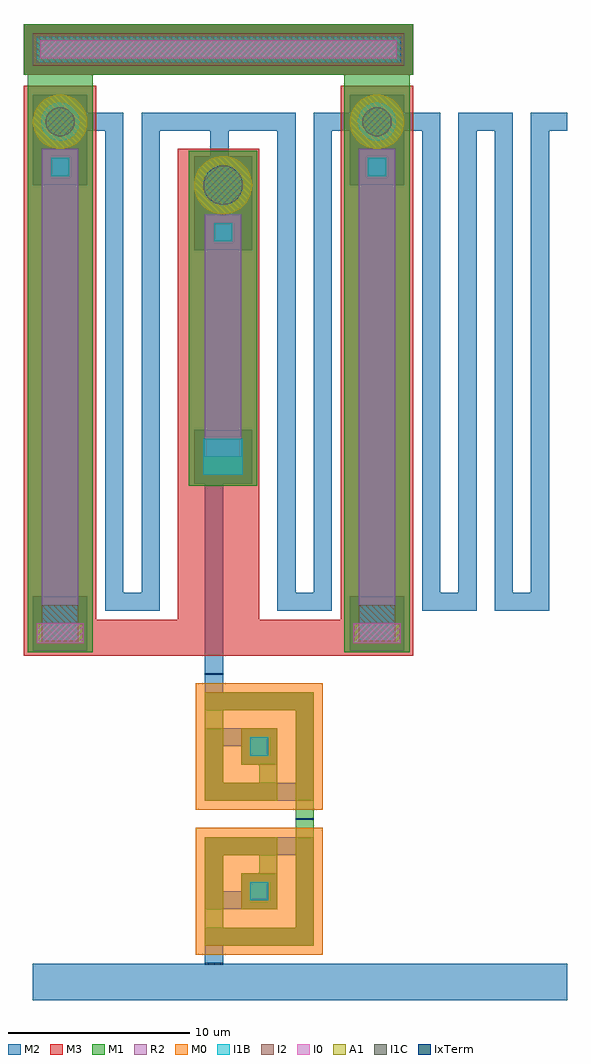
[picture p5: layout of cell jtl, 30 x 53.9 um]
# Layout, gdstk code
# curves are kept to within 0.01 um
from math import pi, radians
import gdstk
lib = gdstk.Library(unit=1e-6, precision=1e-09)
def R(c, l, rs):  # rectangles x0, y0, x1, y1
    for r in rs: c.add(gdstk.rectangle(r[:2], r[2:], *l))
def P(c, l, *ps):  # polygons
    for p in ps: c.add(gdstk.Polygon(p, *l))
M1 = (1, 0)
I1B = (3, 0)
I1C = (4, 0)
A1 = (5, 0)
M2 = (6, 0)
I2 = (8, 0)
R2 = (9, 0)
M3 = (10, 0)
M0 = (30, 0)
I0 = (31, 0)
IxTerm = (63, 0)

circle_3 = lib.new_cell('CIRCLE$3')
P(circle_3, I1C, [(-0.039,-0.8),(-0.195,-0.777),(-0.342,-0.724),(-0.477,-0.643),(-0.593,-0.538),(-0.687,-0.412),(-0.754,-0.27),(-0.792,-0.118),(-0.8,0.039),(-0.777,0.195),(-0.724,0.342),(-0.643,0.477),(-0.538,0.593),(-0.412,0.687),(-0.27,0.754),(-0.118,0.792),(0.039,0.8),(0.195,0.777),(0.342,0.724),(0.477,0.643),(0.593,0.538),(0.687,0.412),(0.754,0.27),(0.792,0.118),(0.8,-0.039),(0.777,-0.195),(0.724,-0.342),(0.643,-0.477),(0.538,-0.593),(0.412,-0.687),(0.27,-0.754),(0.118,-0.792)])

circle = lib.new_cell('CIRCLE')
P(circle, I1B, [(-0.052,-1.05),(-0.255,-1.02),(-0.449,-0.95),(-0.626,-0.844),(-0.779,-0.706),(-0.902,-0.54),(-0.99,-0.354),(-1.04,-0.154),(-1.05,0.052),(-1.02,0.255),(-0.95,0.449),(-0.844,0.626),(-0.706,0.779),(-0.54,0.902),(-0.354,0.99),(-0.154,1.04),(0.052,1.05),(0.255,1.02),(0.449,0.95),(0.626,0.844),(0.779,0.706),(0.902,0.54),(0.99,0.354),(1.04,0.154),(1.05,-0.052),(1.02,-0.255),(0.95,-0.449),(0.844,-0.626),(0.706,-0.779),(0.54,-0.902),(0.354,-0.99),(0.154,-1.04)])

circle_2 = lib.new_cell('CIRCLE$2')
P(circle_2, A1, [(-0.074,-1.5),(-0.365,-1.457),(-0.642,-1.358),(-0.895,-1.206),(-1.113,-1.009),(-1.288,-0.772),(-1.414,-0.506),(-1.486,-0.22),(-1.5,0.074),(-1.457,0.365),(-1.358,0.642),(-1.206,0.895),(-1.009,1.113),(-0.772,1.288),(-0.506,1.414),(-0.22,1.486),(0.074,1.5),(0.365,1.457),(0.642,1.358),(0.895,1.206),(1.113,1.009),(1.288,0.772),(1.414,0.506),(1.486,0.22),(1.5,-0.074),(1.457,-0.365),(1.358,-0.642),(1.206,-0.895),(1.009,-1.113),(0.772,-1.288),(0.506,-1.414),(0.22,-1.486)])

ballisticj = lib.new_cell('BallisticJ')
R(ballisticj, M1, [(-1.8,-1.8,1.8,1.8)])
R(ballisticj, M2, [(-1.5,-1.5,1.5,1.5)])
ballisticj.add(gdstk.Reference(circle_3, (0,0)))
ballisticj.add(gdstk.Reference(circle, (0,0)))
ballisticj.add(gdstk.Reference(circle_2, (0,0)))

ak_qc1p11r906 = lib.new_cell('AK_QC1P11R906')
R(ak_qc1p11r906, I1B, [(-0.9,-27.2,0.9,-25.2), (-0.5,-1.5,0.5,-0.5)])
R(ak_qc1p11r906, M2, [(-1.4,-27.7,1.4,-24.7), (-1.4,-2,1.4,0)])
R(ak_qc1p11r906, R2, [(-1,-26.2,1,0)])

ak_qc1p0j040s = lib.new_cell('AK_QC1P0J040S')
R(ak_qc1p0j040s, M1, [(-1.8,-29.3,1.8,1.8)])
R(ak_qc1p0j040s, I1B, [(-1,-28.7,1,-26.7)])
R(ak_qc1p0j040s, M2, [(-1.5,-29.2,1.5,-26.2), (-1.5,-3.5,1.5,1.5)])
ak_qc1p0j040s.add(gdstk.Reference(ballisticj, (0,0)))
ak_qc1p0j040s.add(gdstk.Reference(ak_qc1p11r906, (0,-1.5)))

ak_qc1p0j040sgd = lib.new_cell('AK_QC1P0J040SGD')
R(ak_qc1p0j040sgd, I2, [(-1,-28.7,1,-26.7)])
R(ak_qc1p0j040sgd, M3, [(-1.5,-29.2,1.5,-26.2)])
R(ak_qc1p0j040sgd, I0, [(-1.3,-28.8,1.3,-27.7)])
ak_qc1p0j040sgd.add(gdstk.Reference(ak_qc1p0j040s, (0,0)))

ak_qc1p0j060 = lib.new_cell('AK_QC1P0J060')
P(ak_qc1p0j060, I1B, [(-0.019,-1.1),(-0.229,-1.076),(-0.43,-1.013),(-0.599,-0.923),(-0.778,-0.778),(-0.923,-0.599),(-1.013,-0.43),(-1.08,-0.21),(-1.1,0.019),(-1.076,0.229),(-1.013,0.43),(-0.923,0.599),(-0.778,0.778),(-0.599,0.923),(-0.43,1.013),(-0.21,1.08),(0.019,1.1),(0.229,1.076),(0.43,1.013),(0.599,0.923),(0.778,0.778),(0.923,0.599),(1.013,0.43),(1.08,0.21),(1.1,-0.019),(1.076,-0.229),(1.013,-0.43),(0.923,-0.599),(0.778,-0.778),(0.599,-0.923),(0.43,-1.013),(0.21,-1.08)])
P(ak_qc1p0j060, I1C, [(-0.12,-1.08),(-0.14,-1.06),(-0.22,-1.06),(-0.24,-1.04),(-0.3,-1.04),(-0.32,-1.02),(-0.42,-1),(-0.58,-0.92),(-0.64,-0.86),(-0.66,-0.86),(-0.86,-0.66),(-0.88,-0.6),(-0.94,-0.54),(-0.98,-0.46),(-0.98,-0.42),(-1.02,-0.36),(-1.02,-0.32),(-1.04,-0.3),(-1.04,-0.24),(-1.06,-0.22),(-1.06,-0.12),(-1.08,-0.1),(-1.08,0.1),(-1.06,0.12),(-1.06,0.24),(-1.04,0.26),(-1.04,0.32),(-0.94,0.54),(-0.9,0.58),(-0.88,0.64),(-0.7,0.82),(-0.68,0.82),(-0.6,0.9),(-0.54,0.92),(-0.5,0.96),(-0.42,1),(-0.32,1.02),(-0.3,1.04),(-0.14,1.06),(-0.12,1.08),(0.12,1.08),(0.14,1.06),(0.22,1.06),(0.24,1.04),(0.3,1.04),(0.32,1.02),(0.42,1),(0.58,0.92),(0.64,0.86),(0.66,0.86),(0.86,0.66),(0.88,0.6),(0.94,0.54),(0.98,0.46),(0.98,0.42),(1.02,0.36),(1.02,0.32),(1.04,0.3),(1.04,0.24),(1.06,0.22),(1.06,0.12),(1.08,0.1),(1.08,-0.1),(1.06,-0.12),(1.06,-0.24),(1.04,-0.26),(1.04,-0.32),(0.94,-0.54),(0.9,-0.58),(0.88,-0.64),(0.7,-0.82),(0.68,-0.82),(0.6,-0.9),(0.54,-0.92),(0.5,-0.96),(0.42,-1),(0.32,-1.02),(0.3,-1.04),(0.14,-1.06),(0.12,-1.08)])
P(ak_qc1p0j060, A1, [(-0.028,-1.6),(-0.333,-1.565),(-0.651,-1.462),(-0.918,-1.311),(-1.151,-1.111),(-1.357,-0.848),(-1.494,-0.573),(-1.576,-0.278),(-1.6,0.028),(-1.565,0.333),(-1.462,0.651),(-1.311,0.918),(-1.111,1.151),(-0.848,1.357),(-0.573,1.494),(-0.278,1.576),(0.028,1.6),(0.333,1.565),(0.651,1.462),(0.918,1.311),(1.151,1.111),(1.357,0.848),(1.494,0.573),(1.576,0.278),(1.6,-0.028),(1.565,-0.333),(1.462,-0.651),(1.311,-0.918),(1.111,-1.151),(0.848,-1.357),(0.573,-1.494),(0.278,-1.576)])

ak_qc1p5r479 = lib.new_cell('AK_QC1P5R479')
R(ak_qc1p5r479, I1B, [(-0.9,-14.4,0.9,-12.4), (-0.5,-1.5,0.5,-0.5)])
R(ak_qc1p5r479, M2, [(-1.4,-14.9,1.4,-11.9), (-1.4,-2,1.4,0)])
R(ak_qc1p5r479, R2, [(-1,-13.4,1,0)])

ak_qc1p0j060s0v700 = lib.new_cell('AK_QC1P0J060S0V700')
R(ak_qc1p0j060s0v700, M1, [(-1.9,-16.6,1.9,1.9)])
R(ak_qc1p0j060s0v700, I1B, [(-1.1,-16,1.1,-14)])
R(ak_qc1p0j060s0v700, M2, [(-1.6,-16.5,1.6,-13.5), (-1.6,-3.6,1.6,1.6)])
ak_qc1p0j060s0v700.add(gdstk.Reference(ak_qc1p0j060, (0,0)))
ak_qc1p0j060s0v700.add(gdstk.Reference(ak_qc1p5r479, (0,-1.6)))

ak6vm21 = lib.new_cell('AK6VM21')
R(ak6vm21, M1, [(-1,-1,1,1)])
R(ak6vm21, I1B, [(-0.5,-0.5,0.5,0.5)])
R(ak6vm21, M2, [(-1,-1,1,1)])

ak6mon103 = lib.new_cell('AK6MON103')
R(ak6mon103, M0, [(-6,0.5,1,7.5)])
ak6mon103.add(gdstk.FlexPath([(0,0),(0,1.5),(-5,1.5),(-5,6.5),(0,6.5),(0,3.5),(-1,3.5),(-1.5,3.5)], 1, ends="flush", simple_path=True, layer=6, datatype=0))  # M2
ak6mon103.add(gdstk.FlexPath([(-3,5),(-3,6.5),(0,6.5),(0,1.5),(-5,1.5),(-5,8)], 1, ends="flush", simple_path=True, layer=1, datatype=0))  # M1
ak6mon103.add(gdstk.FlexPath([(-0.5,0),(0.5,0)], 0.1, ends="flush", simple_path=True, layer=63, datatype=0))  # IxTerm
ak6mon103.add(gdstk.FlexPath([(-5.5,8),(-4.5,8)], 0.1, ends="flush", simple_path=True, layer=63, datatype=0))  # IxTerm
ak6mon103.add(gdstk.Reference(ak6vm21, (-2.5,4)))
ak6mon103.add(gdstk.Label('P1+ M2', (0,0), layer=64, texttype=0))
ak6mon103.add(gdstk.Label('P1- M1', (-5,8), layer=64, texttype=0))

jtl = lib.new_cell('jtl')
R(jtl, M1, [(-14.8,23.35,-11.2,24.15), (2.7,23.35,6.3,24.15)])
R(jtl, M3, [(-15,-7.95,-11,23.55), (-15,-7.95,6.5,-5.95), (-6.5,-7.95,-2,20.05), (2.5,-7.95,6.5,23.55)])
jtl.add(gdstk.FlexPath([(-14.3,25.55),(5.8,25.55)], 1.4, ends="flush", simple_path=True, layer=3, datatype=0))  # I1B
jtl.add(gdstk.FlexPath([(-11.5,21.55),(-10,21.55),(-10,-4.95),(-8,-4.95),(-8,21.55),(-0.5,21.55),(-0.5,-4.95),(1.5,-4.95),(1.5,21.55),(3,21.55)], 1, ends="flush", simple_path=True, layer=6, datatype=0))  # M2
jtl.add(gdstk.FlexPath([(-4.2,21.05),(-4.2,19.65)], 1, ends="flush", simple_path=True, layer=6, datatype=0))  # M2
jtl.add(gdstk.FlexPath([(6,21.55),(7.5,21.55),(7.5,-4.95),(9.5,-4.95),(9.5,21.55),(11.5,21.55),(11.5,-4.95),(13.5,-4.95),(13.5,21.55),(15,21.55)], 1, ends="flush", simple_path=True, layer=6, datatype=0))  # M2
jtl.add(gdstk.FlexPath([(-4.5,2.05),(-4.5,-8.95)], 1, ends="flush", simple_path=True, layer=6, datatype=0))  # M2
jtl.add(gdstk.FlexPath([(-14.5,-25.95),(15,-25.95)], 2, ends="flush", simple_path=True, layer=6, datatype=0))  # M2
jtl.add(gdstk.FlexPath([(-15,25.55),(6.5,25.55)], 2.8, ends="flush", simple_path=True, layer=6, datatype=0))  # M2
jtl.add(gdstk.FlexPath([(-15,25.55),(6.5,25.55)], 2.8, ends="flush", simple_path=True, layer=1, datatype=0))  # M1
jtl.add(gdstk.FlexPath([(-15,25.55),(6.5,25.55)], 2.8, ends="flush", simple_path=True, layer=10, datatype=0))  # M3
jtl.add(gdstk.FlexPath([(-14.5,25.55),(6,25.55)], 1.8, ends="flush", simple_path=True, layer=8, datatype=0))  # I2
jtl.add(gdstk.FlexPath([(-14.1,25.55),(5.6,25.55)], 1, ends="flush", simple_path=True, layer=31, datatype=0))  # I0
jtl.add(gdstk.Reference(ak_qc1p0j040sgd, (-13,21.55)))
jtl.add(gdstk.Reference(ak_qc1p0j040sgd, (4.5,21.55)))
jtl.add(gdstk.Reference(ak_qc1p0j060s0v700, (-4,18.05), rotation=pi, x_reflection=True))
jtl.add(gdstk.Reference(ak6mon103, (-4.5,-8.95), rotation=pi))
jtl.add(gdstk.Reference(ak6mon103, (-4.5,-24.95), rotation=pi, x_reflection=True))

lib.write_gds('jtl.gds')
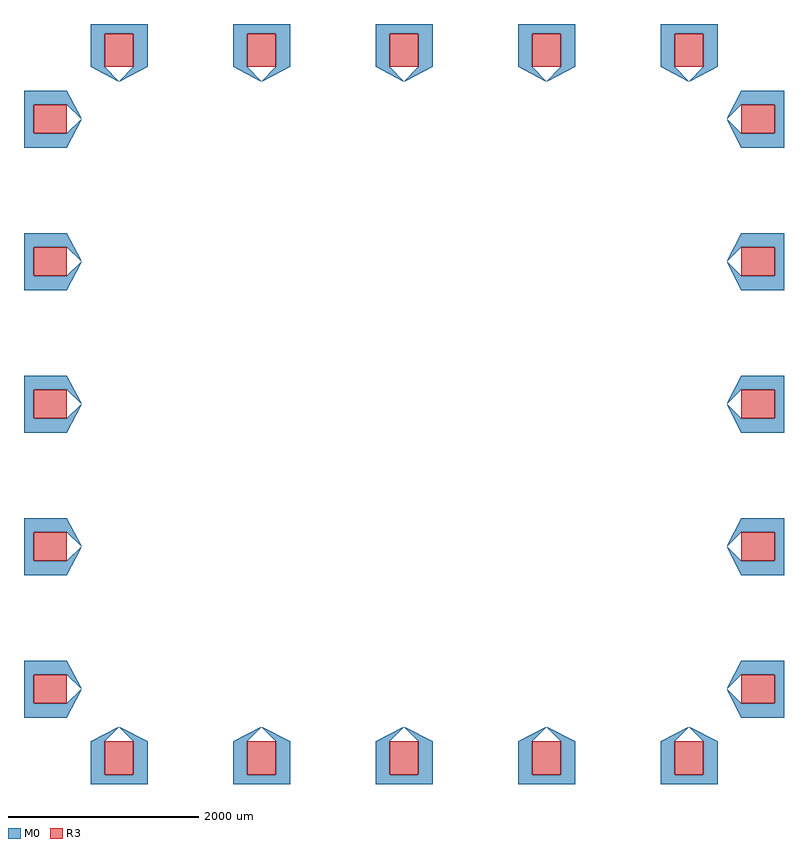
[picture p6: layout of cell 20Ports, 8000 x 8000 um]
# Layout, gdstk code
from math import pi, radians
import gdstk
lib = gdstk.Library(unit=1e-6, precision=1e-09)
def R(c, l, rs):  # rectangles x0, y0, x1, y1
    for r in rs: c.add(gdstk.rectangle(r[:2], r[2:], *l))
def P(c, l, *ps):  # polygons
    for p in ps: c.add(gdstk.Polygon(p, *l))
R3 = (11, 0)
M0 = (30, 0)

launcher = lib.new_cell('launcher')
R(launcher, R3, [(-150,-200,150,150)])
P(launcher, M0, [(-300,-300),(-300,150),(-11,300),(-5,300),(-150,150),(-150,-200),(150,-200),(150,150),(5,300),(11,300),(300,150),(300,-300)])

c_20ports = lib.new_cell('20Ports')
c_20ports.add(gdstk.Reference(launcher, (0,3700), rotation=pi))
c_20ports.add(gdstk.Reference(launcher, (-3700,0), rotation=3*pi/2))
c_20ports.add(gdstk.Reference(launcher, (0,-3700)))
c_20ports.add(gdstk.Reference(launcher, (3700,0), rotation=pi/2))
c_20ports.add(gdstk.Reference(launcher, (3700,1500), rotation=pi/2))
c_20ports.add(gdstk.Reference(launcher, (3700,3000), rotation=pi/2))
c_20ports.add(gdstk.Reference(launcher, (3700,-1500), rotation=pi/2))
c_20ports.add(gdstk.Reference(launcher, (3700,-3000), rotation=pi/2))
c_20ports.add(gdstk.Reference(launcher, (1500,-3700)))
c_20ports.add(gdstk.Reference(launcher, (3000,-3700)))
c_20ports.add(gdstk.Reference(launcher, (-1500,-3700)))
c_20ports.add(gdstk.Reference(launcher, (-3000,-3700)))
c_20ports.add(gdstk.Reference(launcher, (-3700,-3000), rotation=3*pi/2))
c_20ports.add(gdstk.Reference(launcher, (-3700,-1500), rotation=3*pi/2))
c_20ports.add(gdstk.Reference(launcher, (-3700,1500), rotation=3*pi/2))
c_20ports.add(gdstk.Reference(launcher, (-3700,3000), rotation=3*pi/2))
c_20ports.add(gdstk.Reference(launcher, (-1500,3700), rotation=pi))
c_20ports.add(gdstk.Reference(launcher, (1500,3700), rotation=pi))
c_20ports.add(gdstk.Reference(launcher, (3000,3700), rotation=pi))
c_20ports.add(gdstk.Reference(launcher, (-3000,3700), rotation=pi))

lib.write_gds('20Ports.gds')
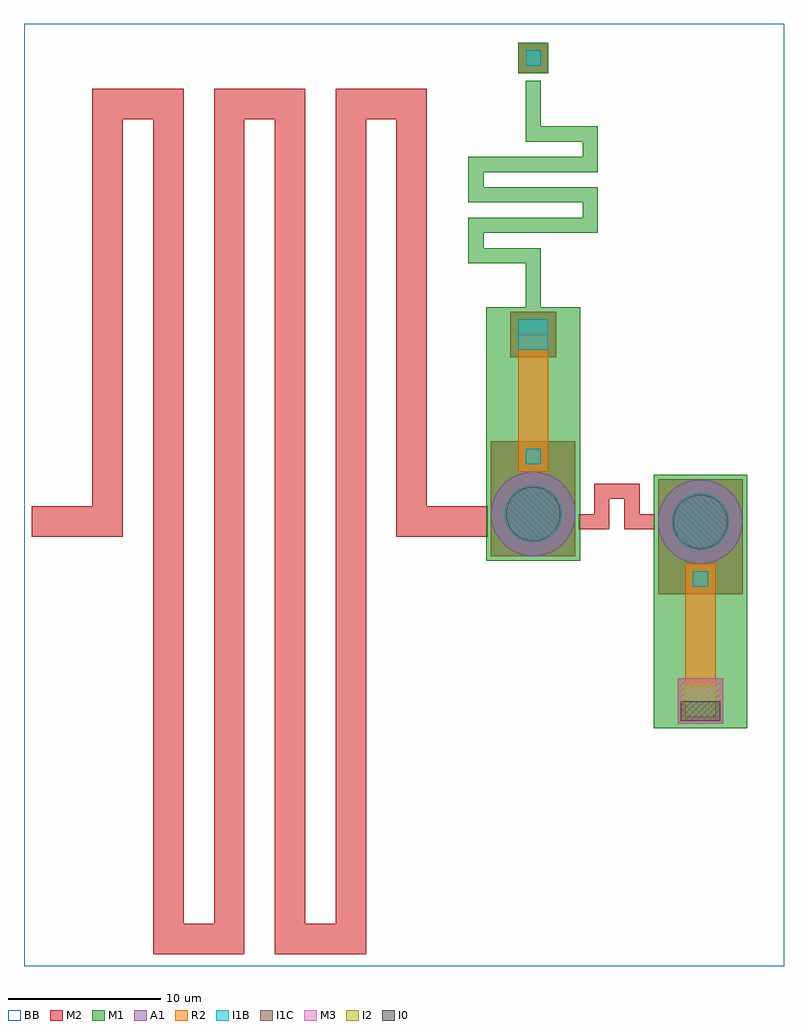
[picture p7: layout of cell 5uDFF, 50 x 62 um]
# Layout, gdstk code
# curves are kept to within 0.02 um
from math import pi, radians
import gdstk
lib = gdstk.Library(unit=1e-6, precision=1e-09)
def R(c, l, rs):  # rectangles x0, y0, x1, y1
    for r in rs: c.add(gdstk.rectangle(r[:2], r[2:], *l))
def P(c, l, *ps):  # polygons
    for p in ps: c.add(gdstk.Polygon(p, *l))
M1 = (1, 0)
BB = (1, 3)
I1B = (3, 0)
I1C = (4, 0)
A1 = (5, 0)
M2 = (6, 0)
I2 = (8, 0)
R2 = (9, 0)
M3 = (10, 0)
I0 = (31, 0)

meanderinductor_21 = lib.new_cell('MeanderInductor$21')
meanderinductor_21.add(gdstk.FlexPath([(-15,0),(-10,0),(-10,27.463),(-6,27.463),(-6,-27.463),(-2,-27.463),(-2,27.463),(2,27.463),(2,-27.463),(6,-27.463),(6,27.463),(10,27.463),(10,0),(15,0)], 2, ends="flush", simple_path=True, layer=6, datatype=0))  # M2

meanderinductor_22 = lib.new_cell('MeanderInductor$22')
meanderinductor_22.add(gdstk.FlexPath([(-7.5,0),(-4,0),(-4,3.758),(-2,3.758),(-2,-3.758),(0,-3.758),(0,3.758),(2,3.758),(2,-3.758),(4,-3.758),(4,0),(7.5,0)], 1, ends="flush", simple_path=True, layer=1, datatype=0))  # M1

jj_26 = lib.new_cell('JJ$26')
R(jj_26, M1, [(-3.079,-13.605,3.079,3.079)])
R(jj_26, I1B, [(-1,-12.805,1,-10.805), (-0.5,-4.279,0.5,-3.279)])
P(jj_26, I1B, [(0,-1.873),(-0.365,-1.837),(-0.717,-1.731),(-1.041,-1.558),(-1.325,-1.325),(-1.558,-1.041),(-1.731,-0.717),(-1.837,-0.365),(-1.873,0),(-1.837,0.365),(-1.731,0.717),(-1.558,1.041),(-1.325,1.325),(-1.041,1.558),(-0.717,1.731),(-0.365,1.837),(0,1.873),(0.365,1.837),(0.717,1.731),(1.041,1.558),(1.325,1.325),(1.558,1.041),(1.731,0.717),(1.837,0.365),(1.873,0),(1.837,-0.365),(1.731,-0.717),(1.558,-1.041),(1.325,-1.325),(1.041,-1.558),(0.717,-1.731),(0.365,-1.837)])
P(jj_26, I1C, [(0,-1.784),(-0.348,-1.75),(-0.683,-1.648),(-0.991,-1.483),(-1.262,-1.262),(-1.483,-0.991),(-1.648,-0.683),(-1.75,-0.348),(-1.784,0),(-1.75,0.348),(-1.648,0.683),(-1.483,0.991),(-1.262,1.262),(-0.991,1.483),(-0.683,1.648),(-0.348,1.75),(0,1.784),(0.348,1.75),(0.683,1.648),(0.991,1.483),(1.262,1.262),(1.483,0.991),(1.648,0.683),(1.75,0.348),(1.784,0),(1.75,-0.348),(1.648,-0.683),(1.483,-0.991),(1.262,-1.262),(0.991,-1.483),(0.683,-1.648),(0.348,-1.75)])
P(jj_26, A1, [(0,-2.78),(-0.542,-2.727),(-1.064,-2.568),(-1.544,-2.311),(-1.966,-1.966),(-2.311,-1.544),(-2.568,-1.064),(-2.727,-0.542),(-2.78,0),(-2.727,0.542),(-2.568,1.064),(-2.311,1.544),(-1.966,1.966),(-1.544,2.311),(-1.064,2.568),(-0.542,2.727),(0,2.78),(0.542,2.727),(1.064,2.568),(1.544,2.311),(1.966,1.966),(2.311,1.544),(2.568,1.064),(2.727,0.542),(2.78,0),(2.727,-0.542),(2.568,-1.064),(2.311,-1.544),(1.966,-1.966),(1.544,-2.311),(1.064,-2.568),(0.542,-2.727)])
R(jj_26, M2, [(-1.5,-13.305,1.5,-10.305), (-2.779,-4.779,2.779,-2.779), (-2.779,-2.779,2.779,2.779)])
jj_26.add(gdstk.FlexPath([(0,-2.779),(0,-11.805)], 2, ends="flush", simple_path=True, layer=9, datatype=0))  # R2

jj_24 = lib.new_cell('JJ$24')
R(jj_24, M1, [(-3.079,-13.605,3.079,3.079)])
R(jj_24, I1B, [(-1,-12.805,1,-10.805), (-0.5,-4.279,0.5,-3.279)])
P(jj_24, I1B, [(0,-1.873),(-0.365,-1.837),(-0.717,-1.731),(-1.041,-1.558),(-1.325,-1.325),(-1.558,-1.041),(-1.731,-0.717),(-1.837,-0.365),(-1.873,0),(-1.837,0.365),(-1.731,0.717),(-1.558,1.041),(-1.325,1.325),(-1.041,1.558),(-0.717,1.731),(-0.365,1.837),(0,1.873),(0.365,1.837),(0.717,1.731),(1.041,1.558),(1.325,1.325),(1.558,1.041),(1.731,0.717),(1.837,0.365),(1.873,0),(1.837,-0.365),(1.731,-0.717),(1.558,-1.041),(1.325,-1.325),(1.041,-1.558),(0.717,-1.731),(0.365,-1.837)])
P(jj_24, I1C, [(0,-1.784),(-0.348,-1.75),(-0.683,-1.648),(-0.991,-1.483),(-1.262,-1.262),(-1.483,-0.991),(-1.648,-0.683),(-1.75,-0.348),(-1.784,0),(-1.75,0.348),(-1.648,0.683),(-1.483,0.991),(-1.262,1.262),(-0.991,1.483),(-0.683,1.648),(-0.348,1.75),(0,1.784),(0.348,1.75),(0.683,1.648),(0.991,1.483),(1.262,1.262),(1.483,0.991),(1.648,0.683),(1.75,0.348),(1.784,0),(1.75,-0.348),(1.648,-0.683),(1.483,-0.991),(1.262,-1.262),(0.991,-1.483),(0.683,-1.648),(0.348,-1.75)])
P(jj_24, A1, [(0,-2.78),(-0.542,-2.727),(-1.064,-2.568),(-1.544,-2.311),(-1.966,-1.966),(-2.311,-1.544),(-2.568,-1.064),(-2.727,-0.542),(-2.78,0),(-2.727,0.542),(-2.568,1.064),(-2.311,1.544),(-1.966,1.966),(-1.544,2.311),(-1.064,2.568),(-0.542,2.727),(0,2.78),(0.542,2.727),(1.064,2.568),(1.544,2.311),(1.966,1.966),(2.311,1.544),(2.568,1.064),(2.727,0.542),(2.78,0),(2.727,-0.542),(2.568,-1.064),(2.311,-1.544),(1.966,-1.966),(1.544,-2.311),(1.064,-2.568),(0.542,-2.727)])
R(jj_24, M2, [(-1.5,-13.305,1.5,-10.305), (-2.779,-4.779,2.779,-2.779), (-2.779,-2.779,2.779,2.779)])
R(jj_24, I2, [(-1,-12.805,1,-10.805)])
R(jj_24, M3, [(-1.5,-13.305,1.5,-10.305)])
R(jj_24, I0, [(-1.3,-13.105,1.3,-11.805)])
jj_24.add(gdstk.FlexPath([(0,-2.779),(0,-11.805)], 2, ends="flush", simple_path=True, layer=9, datatype=0))  # R2

meanderinductor_18 = lib.new_cell('MeanderInductor$18')
meanderinductor_18.add(gdstk.FlexPath([(-2.5,0),(-1,0),(-1,2.006),(1,2.006),(1,0),(2.5,0)], 1, ends="flush", simple_path=True, layer=6, datatype=0))  # M2

via_m2_m1_2 = lib.new_cell('Via$M2-M1$2')
R(via_m2_m1_2, M1, [(-1,-1,1,1)])
R(via_m2_m1_2, I1B, [(-0.5,-0.5,0.5,0.5)])
R(via_m2_m1_2, M2, [(-1,-1,1,1)])

c_5udff = lib.new_cell('5uDFF')
R(c_5udff, BB, [(-5,-29.25,45,32.75)])
c_5udff.add(gdstk.Reference(meanderinductor_21, (10.5,0)))
c_5udff.add(gdstk.Reference(meanderinductor_22, (28.5,21.5), rotation=3*pi/2))
c_5udff.add(gdstk.Reference(jj_26, (28.5,0.5), rotation=pi))
c_5udff.add(gdstk.Reference(jj_24, (39.5,0)))
c_5udff.add(gdstk.Reference(meanderinductor_18, (34,0)))
c_5udff.add(gdstk.Reference(via_m2_m1_2, (28.5,30.5)))

lib.write_gds('5uDFF.gds')
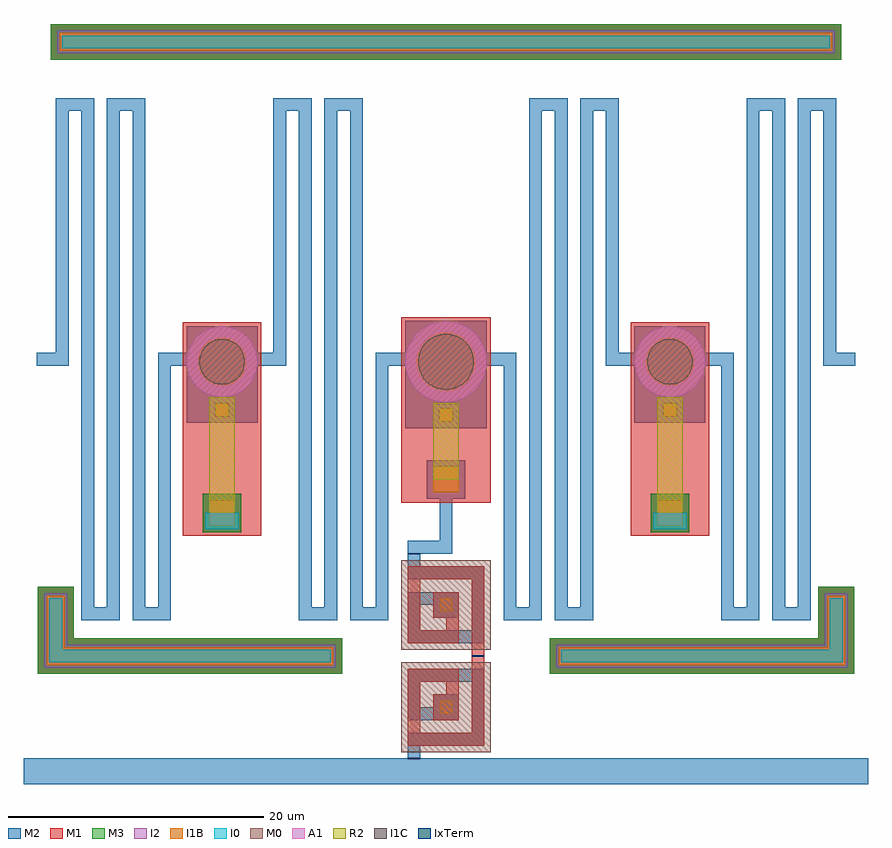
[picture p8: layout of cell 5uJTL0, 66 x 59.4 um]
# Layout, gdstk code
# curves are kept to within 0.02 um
from math import pi, radians
import gdstk
lib = gdstk.Library(unit=1e-6, precision=1e-09)
def R(c, l, rs):  # rectangles x0, y0, x1, y1
    for r in rs: c.add(gdstk.rectangle(r[:2], r[2:], *l))
def P(c, l, *ps):  # polygons
    for p in ps: c.add(gdstk.Polygon(p, *l))
M1 = (1, 0)
I1B = (3, 0)
I1C = (4, 0)
A1 = (5, 0)
M2 = (6, 0)
I2 = (8, 0)
R2 = (9, 0)
M3 = (10, 0)
M0 = (30, 0)
I0 = (31, 0)
IxTerm = (63, 0)

jj_2 = lib.new_cell('JJ$2')
R(jj_2, M1, [(-3.079,-13.605,3.079,3.079)])
R(jj_2, I1B, [(-1,-12.805,1,-10.805), (-0.5,-4.279,0.5,-3.279)])
P(jj_2, I1B, [(0,-1.873),(-0.365,-1.837),(-0.717,-1.731),(-1.041,-1.558),(-1.325,-1.325),(-1.558,-1.041),(-1.731,-0.717),(-1.837,-0.365),(-1.873,0),(-1.837,0.365),(-1.731,0.717),(-1.558,1.041),(-1.325,1.325),(-1.041,1.558),(-0.717,1.731),(-0.365,1.837),(0,1.873),(0.365,1.837),(0.717,1.731),(1.041,1.558),(1.325,1.325),(1.558,1.041),(1.731,0.717),(1.837,0.365),(1.873,0),(1.837,-0.365),(1.731,-0.717),(1.558,-1.041),(1.325,-1.325),(1.041,-1.558),(0.717,-1.731),(0.365,-1.837)])
P(jj_2, I1C, [(0,-1.784),(-0.348,-1.75),(-0.683,-1.648),(-0.991,-1.483),(-1.262,-1.262),(-1.483,-0.991),(-1.648,-0.683),(-1.75,-0.348),(-1.784,0),(-1.75,0.348),(-1.648,0.683),(-1.483,0.991),(-1.262,1.262),(-0.991,1.483),(-0.683,1.648),(-0.348,1.75),(0,1.784),(0.348,1.75),(0.683,1.648),(0.991,1.483),(1.262,1.262),(1.483,0.991),(1.648,0.683),(1.75,0.348),(1.784,0),(1.75,-0.348),(1.648,-0.683),(1.483,-0.991),(1.262,-1.262),(0.991,-1.483),(0.683,-1.648),(0.348,-1.75)])
P(jj_2, A1, [(0,-2.78),(-0.542,-2.727),(-1.064,-2.568),(-1.544,-2.311),(-1.966,-1.966),(-2.311,-1.544),(-2.568,-1.064),(-2.727,-0.542),(-2.78,0),(-2.727,0.542),(-2.568,1.064),(-2.311,1.544),(-1.966,1.966),(-1.544,2.311),(-1.064,2.568),(-0.542,2.727),(0,2.78),(0.542,2.727),(1.064,2.568),(1.544,2.311),(1.966,1.966),(2.311,1.544),(2.568,1.064),(2.727,0.542),(2.78,0),(2.727,-0.542),(2.568,-1.064),(2.311,-1.544),(1.966,-1.966),(1.544,-2.311),(1.064,-2.568),(0.542,-2.727)])
R(jj_2, M2, [(-1.5,-13.305,1.5,-10.305), (-2.779,-4.779,2.779,-2.779), (-2.779,-2.779,2.779,2.779)])
R(jj_2, I2, [(-1,-12.805,1,-10.805)])
R(jj_2, M3, [(-1.5,-13.305,1.5,-10.305)])
R(jj_2, I0, [(-1.3,-13.105,1.3,-11.805)])
jj_2.add(gdstk.FlexPath([(0,-2.779),(0,-11.805)], 2, ends="flush", simple_path=True, layer=9, datatype=0))  # R2

jj_4 = lib.new_cell('JJ$4')
R(jj_4, M1, [(-3.489,-11.007,3.489,3.489)])
R(jj_4, I1B, [(-1,-10.207,1,-8.207), (-0.5,-4.689,0.5,-3.689)])
P(jj_4, I1B, [(0,-2.294),(-0.448,-2.25),(-0.878,-2.12),(-1.275,-1.908),(-1.622,-1.622),(-1.908,-1.275),(-2.12,-0.878),(-2.25,-0.448),(-2.294,0),(-2.25,0.448),(-2.12,0.878),(-1.908,1.275),(-1.622,1.622),(-1.275,1.908),(-0.878,2.12),(-0.448,2.25),(0,2.294),(0.448,2.25),(0.878,2.12),(1.275,1.908),(1.622,1.622),(1.908,1.275),(2.12,0.878),(2.25,0.448),(2.294,0),(2.25,-0.448),(2.12,-0.878),(1.908,-1.275),(1.622,-1.622),(1.275,-1.908),(0.878,-2.12),(0.448,-2.25)])
P(jj_4, I1C, [(0,-2.185),(-0.426,-2.143),(-0.836,-2.019),(-1.214,-1.817),(-1.545,-1.545),(-1.817,-1.214),(-2.019,-0.836),(-2.143,-0.426),(-2.185,0),(-2.143,0.426),(-2.019,0.836),(-1.817,1.214),(-1.545,1.545),(-1.214,1.817),(-0.836,2.019),(-0.426,2.143),(0,2.185),(0.426,2.143),(0.836,2.019),(1.214,1.817),(1.545,1.545),(1.817,1.214),(2.019,0.836),(2.143,0.426),(2.185,0),(2.143,-0.426),(2.019,-0.836),(1.817,-1.214),(1.545,-1.545),(1.214,-1.817),(0.836,-2.019),(0.426,-2.143)])
P(jj_4, A1, [(0,-3.19),(-0.622,-3.129),(-1.221,-2.947),(-1.772,-2.652),(-2.256,-2.256),(-2.652,-1.772),(-2.947,-1.221),(-3.129,-0.622),(-3.19,0),(-3.129,0.622),(-2.947,1.221),(-2.652,1.772),(-2.256,2.256),(-1.772,2.652),(-1.221,2.947),(-0.622,3.129),(0,3.19),(0.622,3.129),(1.221,2.947),(1.772,2.652),(2.256,2.256),(2.652,1.772),(2.947,1.221),(3.129,0.622),(3.19,0),(3.129,-0.622),(2.947,-1.221),(2.652,-1.772),(2.256,-2.256),(1.772,-2.652),(1.221,-2.947),(0.622,-3.129)])
R(jj_4, M2, [(-1.5,-10.707,1.5,-7.707), (-3.19,-5.189,3.19,-3.19), (-3.19,-3.19,3.19,3.19)])
jj_4.add(gdstk.FlexPath([(0,-3.19),(0,-9.207)], 2, ends="flush", simple_path=True, layer=9, datatype=0))  # R2

meanderinductor_3_1 = lib.new_cell('MeanderInductor$3$1')
meanderinductor_3_1.add(gdstk.FlexPath([(-6,0),(-4,0),(-4,19.904),(-2,19.904),(-2,-19.904),(0,-19.904),(0,19.904),(2,19.904),(2,-19.904),(4,-19.904),(4,0),(6,0)], 1, ends="flush", simple_path=True, layer=6, datatype=0))  # M2

ak6vm21 = lib.new_cell('AK6VM21')
R(ak6vm21, M1, [(-1,-1,1,1)])
R(ak6vm21, I1B, [(-0.5,-0.5,0.5,0.5)])
R(ak6vm21, M2, [(-1,-1,1,1)])

ak6mon103 = lib.new_cell('AK6MON103')
R(ak6mon103, M0, [(-6,0.5,1,7.5)])
ak6mon103.add(gdstk.FlexPath([(0,0),(0,1.5),(-5,1.5),(-5,6.5),(0,6.5),(0,3.5),(-1,3.5),(-1.5,3.5)], 1, ends="flush", simple_path=True, layer=6, datatype=0))  # M2
ak6mon103.add(gdstk.FlexPath([(-3,5),(-3,6.5),(0,6.5),(0,1.5),(-5,1.5),(-5,8)], 1, ends="flush", simple_path=True, layer=1, datatype=0))  # M1
ak6mon103.add(gdstk.FlexPath([(-0.5,0),(0.5,0)], 0.1, ends="flush", simple_path=True, layer=63, datatype=0))  # IxTerm
ak6mon103.add(gdstk.FlexPath([(-5.5,8),(-4.5,8)], 0.1, ends="flush", simple_path=True, layer=63, datatype=0))  # IxTerm
ak6mon103.add(gdstk.Reference(ak6vm21, (-2.5,4)))
ak6mon103.add(gdstk.Label('P1+ M2', (0,0), layer=64, texttype=0))
ak6mon103.add(gdstk.Label('P1- M1', (-5,8), layer=64, texttype=0))

via_m3_m0_6_1 = lib.new_cell('Via$M3-M0$6$1')
via_m3_m0_6_1.add(gdstk.FlexPath([(-11.199,0),(11.199,0)], 1.399, ends="flush", simple_path=True, layer=3, datatype=0))  # I1B
via_m3_m0_6_1.add(gdstk.FlexPath([(-11.899,0),(11.899,0)], 2.799, ends="flush", simple_path=True, layer=6, datatype=0))  # M2
via_m3_m0_6_1.add(gdstk.FlexPath([(-11.899,0),(11.899,0)], 2.799, ends="flush", simple_path=True, layer=1, datatype=0))  # M1
via_m3_m0_6_1.add(gdstk.FlexPath([(-11.899,0),(11.899,0)], 2.799, ends="flush", simple_path=True, layer=10, datatype=0))  # M3
via_m3_m0_6_1.add(gdstk.FlexPath([(-11.399,0),(11.399,0)], 1.8, ends="flush", simple_path=True, layer=8, datatype=0))  # I2
via_m3_m0_6_1.add(gdstk.FlexPath([(-11,0),(11,0)], 1, ends="flush", simple_path=True, layer=31, datatype=0))  # I0

via_m3_m0_1_2 = lib.new_cell('Via$M3-M0$1$2')
via_m3_m0_1_2.add(gdstk.FlexPath([(-30.2,0),(30.2,0)], 1.399, ends="flush", simple_path=True, layer=3, datatype=0))  # I1B
via_m3_m0_1_2.add(gdstk.FlexPath([(-30.899,0),(30.899,0)], 2.799, ends="flush", simple_path=True, layer=6, datatype=0))  # M2
via_m3_m0_1_2.add(gdstk.FlexPath([(-30.899,0),(30.899,0)], 2.799, ends="flush", simple_path=True, layer=1, datatype=0))  # M1
via_m3_m0_1_2.add(gdstk.FlexPath([(-30.899,0),(30.899,0)], 2.799, ends="flush", simple_path=True, layer=10, datatype=0))  # M3
via_m3_m0_1_2.add(gdstk.FlexPath([(-30.399,0),(30.399,0)], 1.8, ends="flush", simple_path=True, layer=8, datatype=0))  # I2
via_m3_m0_1_2.add(gdstk.FlexPath([(-30,0),(30,0)], 1, ends="flush", simple_path=True, layer=31, datatype=0))  # I0

via_m3_m0_5 = lib.new_cell('Via$M3-M0$5')
via_m3_m0_5.add(gdstk.FlexPath([(-2.7,0),(2.7,0)], 1.399, ends="flush", simple_path=True, layer=3, datatype=0))  # I1B
via_m3_m0_5.add(gdstk.FlexPath([(-3.4,0),(3.4,0)], 2.799, ends="flush", simple_path=True, layer=6, datatype=0))  # M2
via_m3_m0_5.add(gdstk.FlexPath([(-3.4,0),(3.4,0)], 2.799, ends="flush", simple_path=True, layer=1, datatype=0))  # M1
via_m3_m0_5.add(gdstk.FlexPath([(-3.4,0),(3.4,0)], 2.799, ends="flush", simple_path=True, layer=10, datatype=0))  # M3
via_m3_m0_5.add(gdstk.FlexPath([(-2.9,0),(2.9,0)], 1.8, ends="flush", simple_path=True, layer=8, datatype=0))  # I2
via_m3_m0_5.add(gdstk.FlexPath([(-2.5,0),(2.5,0)], 1, ends="flush", simple_path=True, layer=31, datatype=0))  # I0

c_5ujtl0 = lib.new_cell('5uJTL0')
c_5ujtl0.add(gdstk.FlexPath([(0,-9.5),(0,-14.5),(-3,-14.5)], 1, ends="flush", simple_path=True, layer=6, datatype=0))  # M2
c_5ujtl0.add(gdstk.FlexPath([(-33,-32),(33,-32)], 2, ends="flush", simple_path=True, layer=6, datatype=0))  # M2
c_5ujtl0.add(gdstk.Reference(jj_2, (-17.5,0)))
c_5ujtl0.add(gdstk.Reference(jj_2, (17.5,0)))
c_5ujtl0.add(gdstk.Reference(jj_4, (0,0)))
c_5ujtl0.add(gdstk.Reference(meanderinductor_3_1, (-9,0.201)))
c_5ujtl0.add(gdstk.Reference(meanderinductor_3_1, (9,0.201), x_reflection=True))
c_5ujtl0.add(gdstk.Reference(meanderinductor_3_1, (26,0.201), x_reflection=True))
c_5ujtl0.add(gdstk.Reference(meanderinductor_3_1, (-26,0.201)))
c_5ujtl0.add(gdstk.Reference(ak6mon103, (-2.5,-15), rotation=pi))
c_5ujtl0.add(gdstk.Reference(ak6mon103, (-2.5,-31), rotation=pi, x_reflection=True))
c_5ujtl0.add(gdstk.Reference(via_m3_m0_6_1, (20,-23)))
c_5ujtl0.add(gdstk.Reference(via_m3_m0_6_1, (-20,-23)))
c_5ujtl0.add(gdstk.Reference(via_m3_m0_1_2, (0,25)))
c_5ujtl0.add(gdstk.Reference(via_m3_m0_5, (30.5,-21), rotation=3*pi/2))
c_5ujtl0.add(gdstk.Reference(via_m3_m0_5, (-30.5,-21), rotation=3*pi/2))

lib.write_gds('5uJTL0.gds')
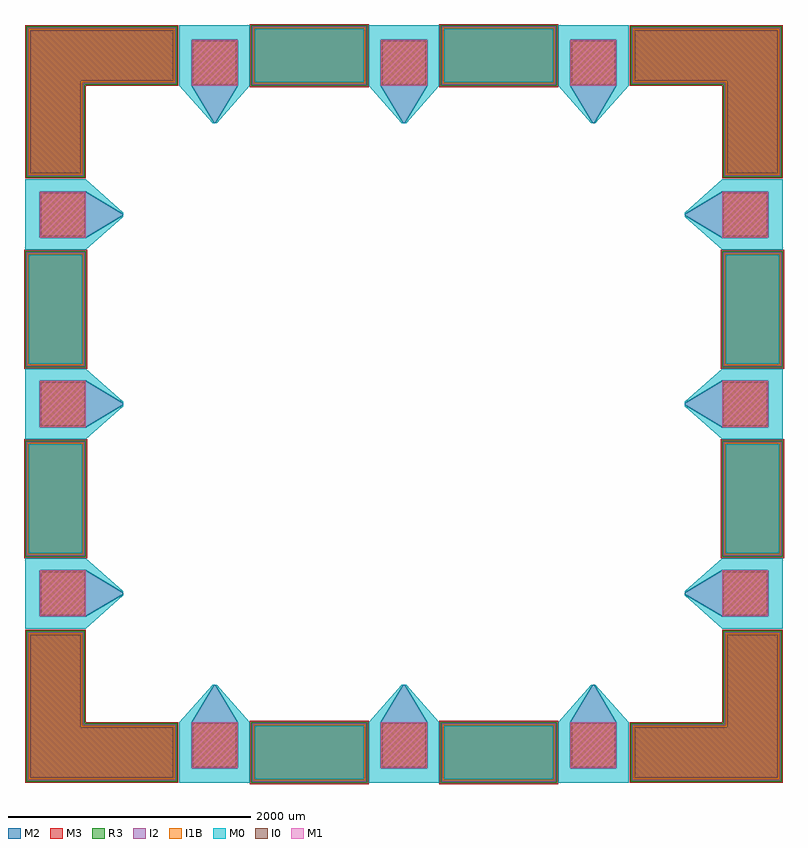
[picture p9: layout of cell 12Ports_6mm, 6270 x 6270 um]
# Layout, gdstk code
from math import pi, radians
import gdstk
lib = gdstk.Library(unit=1e-6, precision=1e-09)
def R(c, l, rs):  # rectangles x0, y0, x1, y1
    for r in rs: c.add(gdstk.rectangle(r[:2], r[2:], *l))
def P(c, l, *ps):  # polygons
    for p in ps: c.add(gdstk.Polygon(p, *l))
M1 = (1, 0)
I1B = (3, 0)
M2 = (6, 0)
I2 = (8, 0)
M3 = (10, 0)
R3 = (11, 0)
M0 = (30, 0)
I0 = (31, 0)

rfpad = lib.new_cell('rfPad')
R(rfpad, M1, [(-190,310,190,690)])
R(rfpad, I1B, [(-182.5,317.5,182.5,682.5)])
R(rfpad, M2, [(-190,310,190,690)])
P(rfpad, M2, [(-5,0),(-190,310),(190,310),(5,0)])
R(rfpad, I2, [(-185,315,185,685)])
R(rfpad, M3, [(-190,310,190,690)])
R(rfpad, R3, [(-187.5,312.5,187.5,687.5)])
R(rfpad, M0, [(-290,310,-190,690), (190,310,290,690), (-290,690,290,810)])
P(rfpad, M0, [(-17,0),(-290,310),(-190,310),(-5,0)],
  [(5,0),(190,310),(290,310),(17,0)])
R(rfpad, I0, [(-180,320,180,680)])

c_6mmcornerpad = lib.new_cell('6mmCornerPad')
P(c_6mmcornerpad, I1B, [(30,-1232.5),(30,-30),(1232.5,-30),(1232.5,-470),(470,-470),(470,-1232.5)])
P(c_6mmcornerpad, M2, [(0,-1262.5),(0,0),(1262.5,0),(1262.5,-500),(500,-500),(500,-1262.5)])
P(c_6mmcornerpad, I2, [(20,-1242.5),(20,-20),(1242.5,-20),(1242.5,-480),(480,-480),(480,-1242.5)])
P(c_6mmcornerpad, M3, [(0,-1262.5),(0,0),(1262.5,0),(1262.5,-500),(500,-500),(500,-1262.5)])
P(c_6mmcornerpad, R3, [(10,-1252.5),(10,-10),(1252.5,-10),(1252.5,-490),(490,-490),(490,-1252.5)])
P(c_6mmcornerpad, I0, [(40,-1222.5),(40,-40),(1222.5,-40),(1222.5,-460),(460,-460),(460,-1222.5)])

c_6mmgroundpad = lib.new_cell('6mmGroundPad')
R(c_6mmgroundpad, I1B, [(-460,-230,460,230)])
R(c_6mmgroundpad, M2, [(-490,-260,490,260)])
R(c_6mmgroundpad, I2, [(-470,-240,470,240)])
R(c_6mmgroundpad, M3, [(-490,-260,490,260)])
R(c_6mmgroundpad, R3, [(-480,-250,480,250)])
R(c_6mmgroundpad, M0, [(-450,-220,450,220)])

c_12ports_6mm = lib.new_cell('12Ports_6mm')
c_12ports_6mm.add(gdstk.Reference(rfpad, (0,2315)))
c_12ports_6mm.add(gdstk.Reference(rfpad, (1562.5,2315)))
c_12ports_6mm.add(gdstk.Reference(rfpad, (-1562.5,2315)))
c_12ports_6mm.add(gdstk.Reference(rfpad, (-2315,1562.5), rotation=pi/2))
c_12ports_6mm.add(gdstk.Reference(rfpad, (-2315,0), rotation=pi/2))
c_12ports_6mm.add(gdstk.Reference(rfpad, (2315,0), rotation=3*pi/2))
c_12ports_6mm.add(gdstk.Reference(rfpad, (2315,1562.5), rotation=3*pi/2))
c_12ports_6mm.add(gdstk.Reference(rfpad, (2315,-1562.5), rotation=3*pi/2))
c_12ports_6mm.add(gdstk.Reference(rfpad, (0,-2315), rotation=pi))
c_12ports_6mm.add(gdstk.Reference(rfpad, (-1562.5,-2315), rotation=pi))
c_12ports_6mm.add(gdstk.Reference(rfpad, (1562.5,-2315), rotation=pi))
c_12ports_6mm.add(gdstk.Reference(rfpad, (-2315,-1562.5), rotation=pi/2))
c_12ports_6mm.add(gdstk.Reference(c_6mmcornerpad, (-3125,3125)))
c_12ports_6mm.add(gdstk.Reference(c_6mmcornerpad, (-3125,-3125), rotation=pi/2))
c_12ports_6mm.add(gdstk.Reference(c_6mmcornerpad, (3125,-3125), rotation=pi))
c_12ports_6mm.add(gdstk.Reference(c_6mmcornerpad, (3125,3125), rotation=3*pi/2))
c_12ports_6mm.add(gdstk.Reference(c_6mmgroundpad, (-781.25,2875)))
c_12ports_6mm.add(gdstk.Reference(c_6mmgroundpad, (781.25,2875)))
c_12ports_6mm.add(gdstk.Reference(c_6mmgroundpad, (-2875,781.25), rotation=pi/2))
c_12ports_6mm.add(gdstk.Reference(c_6mmgroundpad, (-2875,-781.25), rotation=pi/2))
c_12ports_6mm.add(gdstk.Reference(c_6mmgroundpad, (-781.25,-2875), rotation=pi))
c_12ports_6mm.add(gdstk.Reference(c_6mmgroundpad, (781.25,-2875), rotation=pi))
c_12ports_6mm.add(gdstk.Reference(c_6mmgroundpad, (2875,-781.25), rotation=3*pi/2))
c_12ports_6mm.add(gdstk.Reference(c_6mmgroundpad, (2875,781.25), rotation=3*pi/2))

lib.write_gds('12Ports_6mm.gds')
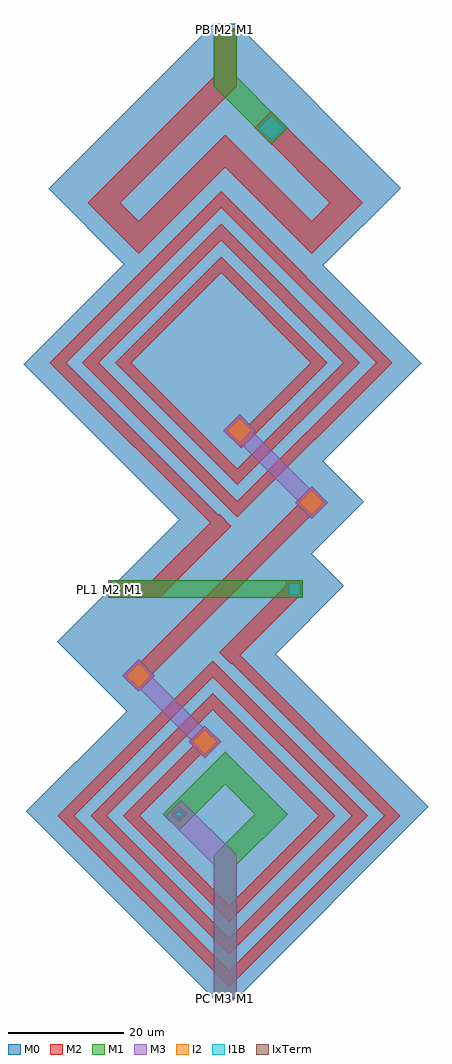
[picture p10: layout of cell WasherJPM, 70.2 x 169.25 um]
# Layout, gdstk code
from math import pi, radians
import gdstk
lib = gdstk.Library(unit=1e-6, precision=1e-09)
def R(c, l, rs):  # rectangles x0, y0, x1, y1
    for r in rs: c.add(gdstk.rectangle(r[:2], r[2:], *l))
def P(c, l, *ps):  # polygons
    for p in ps: c.add(gdstk.Polygon(p, *l))
M1 = (1, 0)
I1B = (3, 0)
M2 = (6, 0)
I2 = (8, 0)
M3 = (10, 0)
M0 = (30, 0)
IxTerm = (63, 0)

squarespiral = lib.new_cell('SquareSpiral')
squarespiral.add(gdstk.FlexPath([(-9,12),(11,12),(11,-12),(-13,-12),(-13,16),(15,16),(15,-16),(-17,-16),(-17,20),(19,20),(19,-20),(-21,-20),(-21,21)], 2, ends="flush", simple_path=True, layer=6, datatype=0))  # M2

via_m3_m2_1_1 = lib.new_cell('Via$M3-M2$1$1')
R(via_m3_m2_1_1, M2, [(-2,-2,2,2)])
R(via_m3_m2_1_1, I2, [(-1.5,-1.5,1.5,1.5)])
R(via_m3_m2_1_1, M3, [(-2,-2,2,2)])

via_m2_m1_3 = lib.new_cell('Via$M2-M1$3')
R(via_m2_m1_3, M1, [(-1.5,-1.5,1.5,1.5)])
R(via_m2_m1_3, I1B, [(-1,-1,1,1)])
R(via_m2_m1_3, M2, [(-1.5,-1.5,1.5,1.5)])

squarespiral_13 = lib.new_cell('SquareSpiral$13')
squarespiral_13.add(gdstk.FlexPath([(-9,12),(11,12),(11,-12),(-13,-12),(-13,16),(15,16),(15,-16),(-17,-16),(-17,20),(19,20),(19,-20),(-21,-20),(-21,21)], 2, ends="flush", simple_path=True, layer=6, datatype=0))  # M2

firstordergradiometer = lib.new_cell('FirstOrderGradiometer')
firstordergradiometer.add(gdstk.FlexPath([(12,0),(0,-12)], 3, ends="flush", simple_path=True, layer=6, datatype=0))  # M2
firstordergradiometer.add(gdstk.FlexPath([(0,12),(-12,0),(-20,0)], 3, ends="flush", simple_path=True, layer=6, datatype=0))  # M2
firstordergradiometer.add(gdstk.FlexPath([(15,15),(-15,-15)], 3, ends="flush", simple_path=True, layer=6, datatype=0))  # M2
firstordergradiometer.add(gdstk.FlexPath([(-20,0),(-14,0)], 3, ends="flush", simple_path=True, layer=6, datatype=0))  # M2
firstordergradiometer.add(gdstk.FlexPath([(11.5,0),(-20,0)], 3, ends="flush", simple_path=True, layer=1, datatype=0))  # M1
firstordergradiometer.add(gdstk.FlexPath([(15,15),(1.75,28.25)], 3, ends="flush", simple_path=True, layer=10, datatype=0))  # M3
firstordergradiometer.add(gdstk.FlexPath([(-15,-15),(-2.778,-27.222)], 3, ends="flush", simple_path=True, layer=10, datatype=0))  # M3
firstordergradiometer.add(gdstk.Reference(squarespiral, (0,-40), rotation=radians(225), x_reflection=True))
firstordergradiometer.add(gdstk.Reference(via_m3_m2_1_1, (2.5,27.5), rotation=radians(45)))
firstordergradiometer.add(gdstk.Reference(via_m3_m2_1_1, (-3.5,-26.5), rotation=radians(45)))
firstordergradiometer.add(gdstk.Reference(via_m3_m2_1_1, (-15,-15), rotation=radians(45)))
firstordergradiometer.add(gdstk.Reference(via_m3_m2_1_1, (15,15), rotation=radians(45)))
firstordergradiometer.add(gdstk.Reference(via_m2_m1_3, (12,0)))
firstordergradiometer.add(gdstk.Reference(squarespiral_13, (0,40), rotation=radians(45), x_reflection=True))

via_m2_m1_5_1 = lib.new_cell('Via$M2-M1$5$1')
R(via_m2_m1_5_1, M1, [(-1,-1,1,1)])
R(via_m2_m1_5_1, I1B, [(-0.5,-0.5,0.5,0.5)])
R(via_m2_m1_5_1, M2, [(-1,-1,1,1)])

via_m3_m2 = lib.new_cell('Via$M3-M2')
R(via_m3_m2, M2, [(-0.5,-0.5,0.5,0.5)])
P(via_m3_m2, I2, [(0,0),(0,0),(0,0),(0,0)])
R(via_m3_m2, M3, [(-0.5,-0.5,0.5,0.5)])

via_m2_m1_1_2 = lib.new_cell('Via$M2-M1$1$2')
R(via_m2_m1_1_2, M1, [(-2,-2,2,2)])
R(via_m2_m1_1_2, I1B, [(-1.5,-1.5,1.5,1.5)])
R(via_m2_m1_1_2, M2, [(-2,-2,2,2)])

jpmbias2 = lib.new_cell('JPMBias2')
jpmbias2.add(gdstk.FlexPath([(0,0),(0,-9),(-21,-30),(-15,-36),(0,-21),(15,-36),(21,-30),(8,-17)], 4, ends="flush", simple_path=True, layer=6, datatype=0))  # M2
jpmbias2.add(gdstk.FlexPath([(8,-17),(0,-9),(0,0)], 4, ends="flush", simple_path=True, layer=1, datatype=0))  # M1
jpmbias2.add(gdstk.Reference(via_m2_m1_1_2, (8,-17), rotation=radians(45)))

washerjpm = lib.new_cell('WasherJPM')
P(washerjpm, M0, [(-2,-71),(-34.454,-38.546),(-17.044,-21.136),(-29.09,-9.09),(-8,12),(-34.954,38.954),(-17.544,56.364),(-30.59,69.41),(-2,98),(2,98),(30.454,69.546),(17.044,56.136),(34.044,39.136),(17.044,22.136),(24.044,15.136),(15.044,6.136),(20.59,0.59),(8.75,-11.25),(35.25,-37.75),(2,-71)])
washerjpm.add(gdstk.FlexPath([(-9.414,-40.414),(0,-31),(8,-39),(0,-47),(0,-50)], 4, ends="flush", simple_path=True, layer=1, datatype=0))  # M1
washerjpm.add(gdstk.FlexPath([(0,-48),(0,-71)], 4, ends="flush", simple_path=True, layer=1, datatype=0))  # M1
washerjpm.add(gdstk.FlexPath([(-9,-38),(0,-47),(0,-71)], 4, ends="flush", simple_path=True, layer=10, datatype=0))  # M3
washerjpm.add(gdstk.FlexPath([(-20,1.5),(-20,-1.5)], 0.5, ends="flush", simple_path=True, layer=63, datatype=0))  # IxTerm
washerjpm.add(gdstk.FlexPath([(-1.5,-71),(1.5,-71)], 0.5, ends="flush", simple_path=True, layer=63, datatype=0))  # IxTerm
washerjpm.add(gdstk.FlexPath([(-2,97),(2,97)], 0.5, ends="flush", simple_path=True, layer=63, datatype=0))  # IxTerm
washerjpm.add(gdstk.Reference(firstordergradiometer, (0,0)))
washerjpm.add(gdstk.Reference(via_m2_m1_5_1, (-8,-39), rotation=radians(45)))
washerjpm.add(gdstk.Reference(via_m3_m2, (-8,-39), rotation=radians(45)))
washerjpm.add(gdstk.Reference(jpmbias2, (0,97)))
washerjpm.add(gdstk.Label('PL1 M2 M1', (-20,0), layer=64, texttype=0))
washerjpm.add(gdstk.Label('PC M3 M1', (0,-71), layer=64, texttype=0))
washerjpm.add(gdstk.Label('PB M2 M1', (0,97), layer=64, texttype=0))

lib.write_gds('WasherJPM.gds')
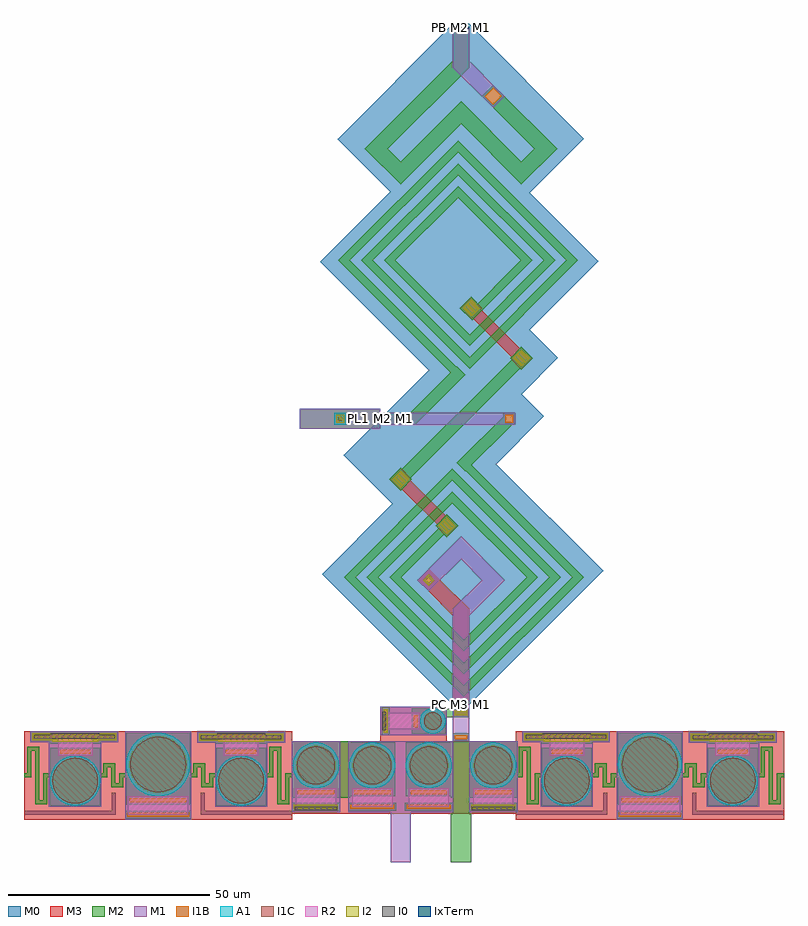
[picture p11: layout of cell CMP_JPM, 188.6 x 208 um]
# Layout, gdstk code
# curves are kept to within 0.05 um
from math import pi, radians
import gdstk
lib = gdstk.Library(unit=1e-6, precision=1e-09)
def R(c, l, rs):  # rectangles x0, y0, x1, y1
    for r in rs: c.add(gdstk.rectangle(r[:2], r[2:], *l))
def P(c, l, *ps):  # polygons
    for p in ps: c.add(gdstk.Polygon(p, *l))
M1 = (1, 0)
I1B = (3, 0)
I1C = (4, 0)
A1 = (5, 0)
M2 = (6, 0)
I2 = (8, 0)
R2 = (9, 0)
M3 = (10, 0)
M0 = (30, 0)
I0 = (31, 0)
IxTerm = (63, 0)

jpmjunction = lib.new_cell('JPMJunction')
R(jpmjunction, M1, [(-2,-2,2,2)])
R(jpmjunction, I1C, [(-0.5,-0.5,0.5,0.5)])
R(jpmjunction, A1, [(-1.5,-1.5,1.5,1.5)])
R(jpmjunction, M2, [(-2,-2,2,2)])
P(jpmjunction, M2, [(0,0),(0,0),(0,0),(0,0)])
R(jpmjunction, I2, [(-1,-1,1,1)])

meanderinductor_3 = lib.new_cell('MeanderInductor$3')
meanderinductor_3.add(gdstk.FlexPath([(-3.25,0),(-2,0),(-2,6.599),(0,6.599),(0,-6.599),(2,-6.599),(2,0),(3.25,0)], 1, ends="flush", simple_path=True, layer=6, datatype=0))  # M2

ak_qc1p2j000 = lib.new_cell('ak_qc1p2j000')
P(ak_qc1p2j000, I1B, [(0,-5.6),(-1.164,-5.478),(-2.188,-5.155),(-3.131,-4.643),(-3.96,-3.96),(-4.643,-3.131),(-5.155,-2.188),(-5.478,-1.164),(-5.6,0),(-5.478,1.164),(-5.155,2.188),(-4.643,3.131),(-3.96,3.96),(-3.131,4.643),(-2.188,5.155),(-1.164,5.478),(0,5.6),(1.164,5.478),(2.188,5.155),(3.131,4.643),(3.96,3.96),(4.643,3.131),(5.155,2.188),(5.478,1.164),(5.6,0),(5.478,-1.164),(5.155,-2.188),(4.643,-3.131),(3.96,-3.96),(3.131,-4.643),(2.188,-5.155),(1.164,-5.478)])
P(ak_qc1p2j000, I1C, [(0,-5.642),(-1.077,-5.538),(-2.113,-5.231),(-3.073,-4.732),(-3.989,-3.989),(-4.732,-3.073),(-5.231,-2.113),(-5.538,-1.077),(-5.642,0),(-5.538,1.077),(-5.231,2.113),(-4.732,3.073),(-3.989,3.989),(-3.073,4.732),(-2.113,5.231),(-1.077,5.538),(0,5.642),(1.077,5.538),(2.113,5.231),(3.073,4.732),(3.989,3.989),(4.732,3.073),(5.231,2.113),(5.538,1.077),(5.642,0),(5.538,-1.077),(5.231,-2.113),(4.732,-3.073),(3.989,-3.989),(3.073,-4.732),(2.113,-5.231),(1.077,-5.538)])
P(ak_qc1p2j000, A1, [(0,-6.2),(-1.183,-6.086),(-2.323,-5.749),(-3.377,-5.2),(-4.384,-4.384),(-5.2,-3.377),(-5.749,-2.323),(-6.086,-1.183),(-6.2,0),(-6.086,1.183),(-5.749,2.323),(-5.2,3.377),(-4.384,4.384),(-3.377,5.2),(-2.323,5.749),(-1.183,6.086),(0,6.2),(1.183,6.086),(2.323,5.749),(3.377,5.2),(4.384,4.384),(5.2,3.377),(5.749,2.323),(6.086,1.183),(6.2,0),(6.086,-1.183),(5.749,-2.323),(5.2,-3.377),(4.384,-4.384),(3.377,-5.2),(2.323,-5.749),(1.183,-6.086)])

ak_qc10r24 = lib.new_cell('ak_qc10r24')
R(ak_qc10r24, I1B, [(-4.1,-5.5,4.2,-3.5), (-3.7,-1.5,3.8,-0.5)])
R(ak_qc10r24, M2, [(-4.6,-6,4.7,-3), (-4.6,-2,4.7,0)])
R(ak_qc10r24, R2, [(-4.2,-4.5,4.3,0)])

ak_qc1p2j000s = lib.new_cell('ak_qc1p2j000s')
R(ak_qc1p2j000s, M1, [(-6.5,-12.3,6.5,6.5)])
R(ak_qc1p2j000s, I1B, [(-5.7,-11.7,5.7,-9.7)])
R(ak_qc1p2j000s, M2, [(-6.2,-12.2,6.2,-9.2), (-6.2,-8.2,6.2,6.2)])
ak_qc1p2j000s.add(gdstk.Reference(ak_qc1p2j000, (0,0)))
ak_qc1p2j000s.add(gdstk.Reference(ak_qc10r24, (0,-6.2)))

ak_qc1p2j000sgd = lib.new_cell('ak_qc1p2j000sgd')
R(ak_qc1p2j000sgd, I2, [(-5.7,-11.7,5.7,-9.7)])
R(ak_qc1p2j000sgd, M3, [(-6.2,-12.2,6.2,-9.2)])
R(ak_qc1p2j000sgd, I0, [(-6,-11.8,6,-10.7)])
ak_qc1p2j000sgd.add(gdstk.Reference(ak_qc1p2j000s, (0,0)))

meanderinductor_5 = lib.new_cell('MeanderInductor$5')
meanderinductor_5.add(gdstk.FlexPath([(-3.25,0),(-2,0),(-2,2.487),(0,2.487),(0,-2.487),(2,-2.487),(2,0),(3.25,0)], 1, ends="flush", simple_path=True, layer=6, datatype=0))  # M2

via_m3_m0_14 = lib.new_cell('Via$M3-M0$14')
via_m3_m0_14.add(gdstk.FlexPath([(-10.199,0),(10.199,0)], 1.399, ends="flush", simple_path=True, layer=3, datatype=0))  # I1B
via_m3_m0_14.add(gdstk.FlexPath([(-10.899,0),(10.899,0)], 2.799, ends="flush", simple_path=True, layer=6, datatype=0))  # M2
via_m3_m0_14.add(gdstk.FlexPath([(-10.899,0),(10.899,0)], 2.799, ends="flush", simple_path=True, layer=1, datatype=0))  # M1
via_m3_m0_14.add(gdstk.FlexPath([(-10.899,0),(10.899,0)], 2.799, ends="flush", simple_path=True, layer=10, datatype=0))  # M3
via_m3_m0_14.add(gdstk.FlexPath([(-10.399,0),(10.399,0)], 1.8, ends="flush", simple_path=True, layer=8, datatype=0))  # I2
via_m3_m0_14.add(gdstk.FlexPath([(-10,0),(10,0)], 1, ends="flush", simple_path=True, layer=31, datatype=0))  # I0

jj_85 = lib.new_cell('JJ$85')
R(jj_85, M1, [(-8.21,-13.722,8.21,8.21)])
R(jj_85, I1B, [(-7.66,-12.922,7.66,-11.922), (-7,-9.41,7,-8.41)])
P(jj_85, I1B, [(0,-7.255),(-1.415,-7.116),(-2.777,-6.703),(-4.031,-6.033),(-5.13,-5.13),(-6.033,-4.031),(-6.703,-2.776),(-7.116,-1.415),(-7.255,0),(-7.116,1.415),(-6.703,2.777),(-6.033,4.031),(-5.13,5.13),(-4.031,6.033),(-2.777,6.703),(-1.415,7.116),(0,7.255),(1.415,7.116),(2.777,6.703),(4.031,6.033),(5.13,5.13),(6.033,4.031),(6.703,2.777),(7.116,1.415),(7.255,0),(7.116,-1.415),(6.703,-2.777),(6.033,-4.031),(5.13,-5.13),(4.031,-6.033),(2.776,-6.703),(1.415,-7.116)])
P(jj_85, I1C, [(0,-6.91),(-1.348,-6.777),(-2.644,-6.384),(-3.839,-5.745),(-4.886,-4.886),(-5.745,-3.839),(-6.384,-2.644),(-6.777,-1.348),(-6.91,0),(-6.777,1.348),(-6.384,2.644),(-5.745,3.839),(-4.886,4.886),(-3.839,5.745),(-2.644,6.384),(-1.348,6.777),(0,6.91),(1.348,6.777),(2.644,6.384),(3.839,5.745),(4.886,4.886),(5.745,3.839),(6.384,2.644),(6.777,1.348),(6.91,0),(6.777,-1.348),(6.384,-2.644),(5.745,-3.839),(4.886,-4.886),(3.839,-5.745),(2.644,-6.384),(1.348,-6.777)])
P(jj_85, A1, [(0,-7.91),(-1.543,-7.758),(-3.027,-7.308),(-4.395,-6.577),(-5.593,-5.593),(-6.577,-4.395),(-7.308,-3.027),(-7.758,-1.543),(-7.91,0),(-7.758,1.543),(-7.308,3.027),(-6.577,4.395),(-5.593,5.593),(-4.395,6.577),(-3.027,7.308),(-1.543,7.758),(0,7.91),(1.543,7.758),(3.027,7.308),(4.395,6.577),(5.593,5.593),(6.577,4.395),(7.308,3.027),(7.758,1.543),(7.91,0),(7.758,-1.543),(7.308,-3.027),(6.577,-4.395),(5.593,-5.593),(4.395,-6.577),(3.027,-7.308),(1.543,-7.758)])
R(jj_85, M2, [(-8.16,-13.422,8.16,-11.422), (-7.91,-9.91,7.91,-7.91), (-7.91,-7.91,7.91,7.91)])
R(jj_85, M3, [(-8.21,-13.722,8.21,8.21)])
jj_85.add(gdstk.FlexPath([(0,-7.91),(0,-12.422)], 15, ends="flush", simple_path=True, layer=9, datatype=0))  # R2

ejtl2 = lib.new_cell('eJTL2')
R(ejtl2, M3, [(-33.2,-11.05,33.4,11)])
ejtl2.add(gdstk.FlexPath([(-10.9,-4.3),(-10.9,-9.3),(-33.2,-9.3)], 1, ends="flush", simple_path=True, layer=30, datatype=0))  # M0
ejtl2.add(gdstk.FlexPath([(11.1,-4.3),(11.1,-9.3),(33.4,-9.3)], 1, ends="flush", simple_path=True, layer=30, datatype=0))  # M0
ejtl2.add(gdstk.Reference(meanderinductor_3, (-29.95,0)))
ejtl2.add(gdstk.Reference(meanderinductor_3, (30.15,0)))
ejtl2.add(gdstk.Reference(ak_qc1p2j000sgd, (-20.5,-1.3), x_reflection=True))
ejtl2.add(gdstk.Reference(ak_qc1p2j000sgd, (20.7,-1.3), rotation=pi))
ejtl2.add(gdstk.Reference(meanderinductor_5, (-11.05,0)))
ejtl2.add(gdstk.Reference(meanderinductor_5, (11.25,0)))
ejtl2.add(gdstk.Reference(via_m3_m0_14, (-20.7,9.6)))
ejtl2.add(gdstk.Reference(via_m3_m0_14, (20.7,9.5)))
ejtl2.add(gdstk.Reference(jj_85, (0.1,2.7)))

squarespiral = lib.new_cell('SquareSpiral')
squarespiral.add(gdstk.FlexPath([(-9,12),(11,12),(11,-12),(-13,-12),(-13,16),(15,16),(15,-16),(-17,-16),(-17,20),(19,20),(19,-20),(-21,-20),(-21,21)], 2, ends="flush", simple_path=True, layer=6, datatype=0))  # M2

via_m3_m2_1_1 = lib.new_cell('Via$M3-M2$1$1')
R(via_m3_m2_1_1, M2, [(-2,-2,2,2)])
R(via_m3_m2_1_1, I2, [(-1.5,-1.5,1.5,1.5)])
R(via_m3_m2_1_1, M3, [(-2,-2,2,2)])

via_m2_m1_3 = lib.new_cell('Via$M2-M1$3')
R(via_m2_m1_3, M1, [(-1.5,-1.5,1.5,1.5)])
R(via_m2_m1_3, I1B, [(-1,-1,1,1)])
R(via_m2_m1_3, M2, [(-1.5,-1.5,1.5,1.5)])

squarespiral_13 = lib.new_cell('SquareSpiral$13')
squarespiral_13.add(gdstk.FlexPath([(-9,12),(11,12),(11,-12),(-13,-12),(-13,16),(15,16),(15,-16),(-17,-16),(-17,20),(19,20),(19,-20),(-21,-20),(-21,21)], 2, ends="flush", simple_path=True, layer=6, datatype=0))  # M2

firstordergradiometer = lib.new_cell('FirstOrderGradiometer')
firstordergradiometer.add(gdstk.FlexPath([(12,0),(0,-12)], 3, ends="flush", simple_path=True, layer=6, datatype=0))  # M2
firstordergradiometer.add(gdstk.FlexPath([(0,12),(-12,0),(-20,0)], 3, ends="flush", simple_path=True, layer=6, datatype=0))  # M2
firstordergradiometer.add(gdstk.FlexPath([(15,15),(-15,-15)], 3, ends="flush", simple_path=True, layer=6, datatype=0))  # M2
firstordergradiometer.add(gdstk.FlexPath([(-20,0),(-14,0)], 3, ends="flush", simple_path=True, layer=6, datatype=0))  # M2
firstordergradiometer.add(gdstk.FlexPath([(11.5,0),(-20,0)], 3, ends="flush", simple_path=True, layer=1, datatype=0))  # M1
firstordergradiometer.add(gdstk.FlexPath([(15,15),(1.75,28.25)], 3, ends="flush", simple_path=True, layer=10, datatype=0))  # M3
firstordergradiometer.add(gdstk.FlexPath([(-15,-15),(-2.778,-27.222)], 3, ends="flush", simple_path=True, layer=10, datatype=0))  # M3
firstordergradiometer.add(gdstk.Reference(squarespiral, (0,-40), rotation=radians(225), x_reflection=True))
firstordergradiometer.add(gdstk.Reference(via_m3_m2_1_1, (2.5,27.5), rotation=radians(45)))
firstordergradiometer.add(gdstk.Reference(via_m3_m2_1_1, (-3.5,-26.5), rotation=radians(45)))
firstordergradiometer.add(gdstk.Reference(via_m3_m2_1_1, (-15,-15), rotation=radians(45)))
firstordergradiometer.add(gdstk.Reference(via_m3_m2_1_1, (15,15), rotation=radians(45)))
firstordergradiometer.add(gdstk.Reference(via_m2_m1_3, (12,0)))
firstordergradiometer.add(gdstk.Reference(squarespiral_13, (0,40), rotation=radians(45), x_reflection=True))

jj_103 = lib.new_cell('JJ$103')
R(jj_103, M1, [(-6.019,-11.578,6.019,6.019)])
R(jj_103, I1B, [(-5.47,-10.778,5.47,-9.778), (-4.5,-7.22,4.5,-6.22)])
P(jj_103, I1B, [(0,-4.956),(-0.967,-4.861),(-1.897,-4.579),(-2.754,-4.121),(-3.505,-3.505),(-4.121,-2.754),(-4.579,-1.897),(-4.861,-0.967),(-4.956,0),(-4.861,0.967),(-4.579,1.897),(-4.121,2.754),(-3.505,3.505),(-2.754,4.121),(-1.897,4.579),(-0.967,4.861),(0,4.956),(0.967,4.861),(1.897,4.579),(2.754,4.121),(3.505,3.505),(4.121,2.754),(4.579,1.897),(4.861,0.967),(4.956,0),(4.861,-0.967),(4.579,-1.897),(4.121,-2.754),(3.505,-3.505),(2.754,-4.121),(1.897,-4.579),(0.967,-4.861)])
P(jj_103, I1C, [(0,-4.72),(-0.921,-4.63),(-1.806,-4.361),(-2.623,-3.925),(-3.338,-3.338),(-3.925,-2.622),(-4.361,-1.806),(-4.63,-0.921),(-4.72,0),(-4.63,0.921),(-4.361,1.806),(-3.925,2.622),(-3.338,3.338),(-2.622,3.925),(-1.806,4.361),(-0.921,4.63),(0,4.72),(0.921,4.63),(1.806,4.361),(2.622,3.925),(3.338,3.338),(3.925,2.622),(4.361,1.806),(4.63,0.921),(4.72,0),(4.63,-0.921),(4.361,-1.806),(3.925,-2.623),(3.338,-3.338),(2.622,-3.925),(1.806,-4.361),(0.921,-4.63)])
P(jj_103, A1, [(0,-5.72),(-1.116,-5.61),(-2.189,-5.285),(-3.178,-4.756),(-4.045,-4.045),(-4.756,-3.178),(-5.285,-2.189),(-5.61,-1.116),(-5.72,0),(-5.61,1.116),(-5.285,2.189),(-4.756,3.178),(-4.045,4.045),(-3.178,4.756),(-2.189,5.285),(-1.116,5.61),(0,5.72),(1.116,5.61),(2.189,5.285),(3.178,4.756),(4.045,4.045),(4.756,3.178),(5.285,2.189),(5.61,1.116),(5.72,0),(5.61,-1.116),(5.285,-2.189),(4.756,-3.178),(4.045,-4.045),(3.178,-4.756),(2.189,-5.285),(1.116,-5.61)])
R(jj_103, M2, [(-5.97,-11.278,5.97,-9.278), (-5.72,-7.72,5.72,-5.72), (-5.72,-5.72,5.72,5.72)])
R(jj_103, I2, [(-5.47,-10.778,5.47,-9.778)])
R(jj_103, M3, [(-6.019,-11.578,6.019,6.019), (-5.97,-11.278,5.97,-9.278)])
R(jj_103, I0, [(-5.3,-11.078,5.3,-10.278)])
jj_103.add(gdstk.FlexPath([(0,-5.72),(0,-10.278)], 10, ends="flush", simple_path=True, layer=9, datatype=0))  # R2

jj_104 = lib.new_cell('JJ$104')
R(jj_104, M1, [(-6.019,-11.578,6.019,6.019)])
R(jj_104, I1B, [(-5.47,-10.778,5.47,-9.778), (-4.5,-7.22,4.5,-6.22)])
P(jj_104, I1B, [(0,-4.956),(-0.967,-4.861),(-1.897,-4.579),(-2.754,-4.121),(-3.505,-3.505),(-4.121,-2.754),(-4.579,-1.897),(-4.861,-0.967),(-4.956,0),(-4.861,0.967),(-4.579,1.897),(-4.121,2.754),(-3.505,3.505),(-2.754,4.121),(-1.897,4.579),(-0.967,4.861),(0,4.956),(0.967,4.861),(1.897,4.579),(2.754,4.121),(3.505,3.505),(4.121,2.754),(4.579,1.897),(4.861,0.967),(4.956,0),(4.861,-0.967),(4.579,-1.897),(4.121,-2.754),(3.505,-3.505),(2.754,-4.121),(1.897,-4.579),(0.967,-4.861)])
P(jj_104, I1C, [(0,-4.72),(-0.921,-4.63),(-1.806,-4.361),(-2.623,-3.925),(-3.338,-3.338),(-3.925,-2.622),(-4.361,-1.806),(-4.63,-0.921),(-4.72,0),(-4.63,0.921),(-4.361,1.806),(-3.925,2.622),(-3.338,3.338),(-2.622,3.925),(-1.806,4.361),(-0.921,4.63),(0,4.72),(0.921,4.63),(1.806,4.361),(2.622,3.925),(3.338,3.338),(3.925,2.622),(4.361,1.806),(4.63,0.921),(4.72,0),(4.63,-0.921),(4.361,-1.806),(3.925,-2.623),(3.338,-3.338),(2.622,-3.925),(1.806,-4.361),(0.921,-4.63)])
P(jj_104, A1, [(0,-5.72),(-1.116,-5.61),(-2.189,-5.285),(-3.178,-4.756),(-4.045,-4.045),(-4.756,-3.178),(-5.285,-2.189),(-5.61,-1.116),(-5.72,0),(-5.61,1.116),(-5.285,2.189),(-4.756,3.178),(-4.045,4.045),(-3.178,4.756),(-2.189,5.285),(-1.116,5.61),(0,5.72),(1.116,5.61),(2.189,5.285),(3.178,4.756),(4.045,4.045),(4.756,3.178),(5.285,2.189),(5.61,1.116),(5.72,0),(5.61,-1.116),(5.285,-2.189),(4.756,-3.178),(4.045,-4.045),(3.178,-4.756),(2.189,-5.285),(1.116,-5.61)])
R(jj_104, M2, [(-5.97,-11.278,5.97,-9.278), (-5.72,-7.72,5.72,-5.72), (-5.72,-5.72,5.72,5.72)])
R(jj_104, M3, [(-6.019,-11.578,6.019,6.019)])
jj_104.add(gdstk.FlexPath([(0,-5.72),(0,-10.278)], 10, ends="flush", simple_path=True, layer=9, datatype=0))  # R2

via_m2_m1_1_2 = lib.new_cell('Via$M2-M1$1$2')
R(via_m2_m1_1_2, M1, [(-2,-2,2,2)])
R(via_m2_m1_1_2, I1B, [(-1.5,-1.5,1.5,1.5)])
R(via_m2_m1_1_2, M2, [(-2,-2,2,2)])

jpmbias2 = lib.new_cell('JPMBias2')
jpmbias2.add(gdstk.FlexPath([(0,0),(0,-9),(-21,-30),(-15,-36),(0,-21),(15,-36),(21,-30),(8,-17)], 4, ends="flush", simple_path=True, layer=6, datatype=0))  # M2
jpmbias2.add(gdstk.FlexPath([(8,-17),(0,-9),(0,0)], 4, ends="flush", simple_path=True, layer=1, datatype=0))  # M1
jpmbias2.add(gdstk.Reference(via_m2_m1_1_2, (8,-17), rotation=radians(45)))

jj_102 = lib.new_cell('JJ$102')
R(jj_102, M1, [(-6.019,-11.578,6.019,6.019)])
R(jj_102, I1B, [(-5.47,-10.778,5.47,-9.778), (-4.5,-7.22,4.5,-6.22)])
P(jj_102, I1B, [(0,-4.956),(-0.967,-4.861),(-1.897,-4.579),(-2.754,-4.121),(-3.505,-3.505),(-4.121,-2.754),(-4.579,-1.897),(-4.861,-0.967),(-4.956,0),(-4.861,0.967),(-4.579,1.897),(-4.121,2.754),(-3.505,3.505),(-2.754,4.121),(-1.897,4.579),(-0.967,4.861),(0,4.956),(0.967,4.861),(1.897,4.579),(2.754,4.121),(3.505,3.505),(4.121,2.754),(4.579,1.897),(4.861,0.967),(4.956,0),(4.861,-0.967),(4.579,-1.897),(4.121,-2.754),(3.505,-3.505),(2.754,-4.121),(1.897,-4.579),(0.967,-4.861)])
P(jj_102, I1C, [(0,-4.72),(-0.921,-4.63),(-1.806,-4.361),(-2.623,-3.925),(-3.338,-3.338),(-3.925,-2.622),(-4.361,-1.806),(-4.63,-0.921),(-4.72,0),(-4.63,0.921),(-4.361,1.806),(-3.925,2.622),(-3.338,3.338),(-2.622,3.925),(-1.806,4.361),(-0.921,4.63),(0,4.72),(0.921,4.63),(1.806,4.361),(2.622,3.925),(3.338,3.338),(3.925,2.622),(4.361,1.806),(4.63,0.921),(4.72,0),(4.63,-0.921),(4.361,-1.806),(3.925,-2.623),(3.338,-3.338),(2.622,-3.925),(1.806,-4.361),(0.921,-4.63)])
P(jj_102, A1, [(0,-5.72),(-1.116,-5.61),(-2.189,-5.285),(-3.178,-4.756),(-4.045,-4.045),(-4.756,-3.178),(-5.285,-2.189),(-5.61,-1.116),(-5.72,0),(-5.61,1.116),(-5.285,2.189),(-4.756,3.178),(-4.045,4.045),(-3.178,4.756),(-2.189,5.285),(-1.116,5.61),(0,5.72),(1.116,5.61),(2.189,5.285),(3.178,4.756),(4.045,4.045),(4.756,3.178),(5.285,2.189),(5.61,1.116),(5.72,0),(5.61,-1.116),(5.285,-2.189),(4.756,-3.178),(4.045,-4.045),(3.178,-4.756),(2.189,-5.285),(1.116,-5.61)])
R(jj_102, M2, [(-5.97,-11.278,5.97,-9.278), (-5.72,-7.72,5.72,-5.72), (-5.72,-5.72,5.72,5.72)])
R(jj_102, M3, [(-6.019,-11.578,6.019,6.019)])
jj_102.add(gdstk.FlexPath([(0,-5.72),(0,-10.278)], 10, ends="flush", simple_path=True, layer=9, datatype=0))  # R2

jj_105 = lib.new_cell('JJ$105')
R(jj_105, M1, [(-6.019,-11.578,6.019,6.019)])
R(jj_105, I1B, [(-5.47,-10.778,5.47,-9.778), (-4.5,-7.22,4.5,-6.22)])
P(jj_105, I1B, [(0,-4.956),(-0.967,-4.861),(-1.897,-4.579),(-2.754,-4.121),(-3.505,-3.505),(-4.121,-2.754),(-4.579,-1.897),(-4.861,-0.967),(-4.956,0),(-4.861,0.967),(-4.579,1.897),(-4.121,2.754),(-3.505,3.505),(-2.754,4.121),(-1.897,4.579),(-0.967,4.861),(0,4.956),(0.967,4.861),(1.897,4.579),(2.754,4.121),(3.505,3.505),(4.121,2.754),(4.579,1.897),(4.861,0.967),(4.956,0),(4.861,-0.967),(4.579,-1.897),(4.121,-2.754),(3.505,-3.505),(2.754,-4.121),(1.897,-4.579),(0.967,-4.861)])
P(jj_105, I1C, [(0,-4.72),(-0.921,-4.63),(-1.806,-4.361),(-2.623,-3.925),(-3.338,-3.338),(-3.925,-2.622),(-4.361,-1.806),(-4.63,-0.921),(-4.72,0),(-4.63,0.921),(-4.361,1.806),(-3.925,2.622),(-3.338,3.338),(-2.622,3.925),(-1.806,4.361),(-0.921,4.63),(0,4.72),(0.921,4.63),(1.806,4.361),(2.622,3.925),(3.338,3.338),(3.925,2.622),(4.361,1.806),(4.63,0.921),(4.72,0),(4.63,-0.921),(4.361,-1.806),(3.925,-2.623),(3.338,-3.338),(2.622,-3.925),(1.806,-4.361),(0.921,-4.63)])
P(jj_105, A1, [(0,-5.72),(-1.116,-5.61),(-2.189,-5.285),(-3.178,-4.756),(-4.045,-4.045),(-4.756,-3.178),(-5.285,-2.189),(-5.61,-1.116),(-5.72,0),(-5.61,1.116),(-5.285,2.189),(-4.756,3.178),(-4.045,4.045),(-3.178,4.756),(-2.189,5.285),(-1.116,5.61),(0,5.72),(1.116,5.61),(2.189,5.285),(3.178,4.756),(4.045,4.045),(4.756,3.178),(5.285,2.189),(5.61,1.116),(5.72,0),(5.61,-1.116),(5.285,-2.189),(4.756,-3.178),(4.045,-4.045),(3.178,-4.756),(2.189,-5.285),(1.116,-5.61)])
R(jj_105, M2, [(-5.97,-11.278,5.97,-9.278), (-5.72,-7.72,5.72,-5.72), (-5.72,-5.72,5.72,5.72)])
R(jj_105, I2, [(-5.47,-10.778,5.47,-9.778)])
R(jj_105, M3, [(-6.019,-11.578,6.019,6.019), (-5.97,-11.278,5.97,-9.278)])
R(jj_105, I0, [(-5.3,-11.078,5.3,-10.278)])
jj_105.add(gdstk.FlexPath([(0,-5.72),(0,-10.278)], 10, ends="flush", simple_path=True, layer=9, datatype=0))  # R2

jj_96 = lib.new_cell('JJ$96')
R(jj_96, M1, [(-3.489,-12.999,3.489,3.489)])
R(jj_96, I1B, [(-2.94,-12.199,2.94,-11.199), (-1.5,-4.689,1.5,-3.689)])
P(jj_96, I1B, [(0,-2.294),(-0.878,-2.12),(-1.622,-1.622),(-2.12,-0.878),(-2.294,0),(-2.12,0.878),(-1.622,1.622),(-0.878,2.12),(0,2.294),(0.878,2.12),(1.622,1.622),(2.12,0.878),(2.294,0),(2.12,-0.878),(1.622,-1.622),(0.878,-2.12)])
P(jj_96, I1C, [(0,-2.185),(-0.836,-2.019),(-1.545,-1.545),(-2.019,-0.836),(-2.185,0),(-2.019,0.836),(-1.545,1.545),(-0.836,2.019),(0,2.185),(0.836,2.019),(1.545,1.545),(2.019,0.836),(2.185,0),(2.019,-0.836),(1.545,-1.545),(0.836,-2.019)])
P(jj_96, A1, [(0,-3.19),(-0.622,-3.129),(-1.221,-2.947),(-1.772,-2.652),(-2.256,-2.256),(-2.652,-1.772),(-2.947,-1.221),(-3.129,-0.622),(-3.19,0),(-3.129,0.622),(-2.947,1.221),(-2.652,1.772),(-2.256,2.256),(-1.772,2.652),(-1.221,2.947),(-0.622,3.129),(0,3.19),(0.622,3.129),(1.221,2.947),(1.772,2.652),(2.256,2.256),(2.652,1.772),(2.947,1.221),(3.129,0.622),(3.19,0),(3.129,-0.622),(2.947,-1.221),(2.652,-1.772),(2.256,-2.256),(1.772,-2.652),(1.221,-2.947),(0.622,-3.129)])
R(jj_96, M2, [(-3.44,-12.699,3.44,-10.699), (-3.19,-5.189,3.19,-3.19), (-3.19,-3.19,3.19,3.19)])
R(jj_96, I2, [(-2.94,-12.199,2.94,-11.199)])
R(jj_96, M3, [(-3.489,-12.999,3.489,3.489), (-3.44,-12.699,3.44,-10.699)])
R(jj_96, I0, [(-2.3,-12.499,2.3,-11.699)])
jj_96.add(gdstk.FlexPath([(0,-3.19),(0,-11.699)], 4, ends="flush", simple_path=True, layer=9, datatype=0))  # R2

via_m2_m1_5 = lib.new_cell('Via$M2-M1$5')
R(via_m2_m1_5, M1, [(-2,-1,2,1)])
R(via_m2_m1_5, I1B, [(-1.5,-0.5,1.5,0.5)])
R(via_m2_m1_5, M2, [(-2,-1,2,1)])

washerinductor = lib.new_cell('WasherInductor')
P(washerinductor, I1B, [(-8,31.293),(-8.707,32),(-8,32.707),(-7.293,32)])
P(washerinductor, I2, [(-8,30.586),(-9.414,32),(-8,33.414),(-6.586,32)])
P(washerinductor, M3, [(-8,29.172),(-10.828,32),(-8,34.828),(-5.172,32)])
washerinductor.add(gdstk.FlexPath([(-9.414,30.586),(0,40),(8,32),(0,24),(0,0)], 4, ends="flush", simple_path=True, layer=1, datatype=0))  # M1
washerinductor.add(gdstk.FlexPath([(-6.586,30.586),(0,24),(0,0)], 4, ends="flush", simple_path=True, layer=10, datatype=0))  # M3

via_m3_m2_3 = lib.new_cell('Via$M3-M2$3')
R(via_m3_m2_3, M2, [(-2,-1,2,1)])
R(via_m3_m2_3, I2, [(-1.5,-0.5,1.5,0.5)])
R(via_m3_m2_3, M3, [(-2,-1,2,1)])

cmp_jpm = lib.new_cell('CMP_JPM')
R(cmp_jpm, M1, [(-16,-97.578,-14.019,-79.981)])
R(cmp_jpm, M2, [(-42,-94,-27.5,-80), (-2.5,-94,14,-80)])
R(cmp_jpm, M3, [(-42.5,-98,14.5,-80), (-19.999,-79.989,-3.511,-71.511)])
P(cmp_jpm, M0, [(-2,-71),(-34.454,-38.546),(-17.044,-21.136),(-29.09,-9.09),(-8,12),(-34.954,38.954),(-17.544,56.364),(-30.59,69.41),(-2,98),(2,98),(30.454,69.546),(17.044,56.136),(34.044,39.136),(17.044,22.136),(24.044,15.136),(15.044,6.136),(20.59,0.59),(8.75,-11.25),(35.25,-37.75),(2,-71)])
cmp_jpm.add(gdstk.FlexPath([(-20,0),(-40,0)], 5, ends="flush", simple_path=True, layer=6, datatype=0))  # M2
cmp_jpm.add(gdstk.FlexPath([(0,-110),(0,-98)], 5, ends="flush", simple_path=True, layer=6, datatype=0))  # M2
cmp_jpm.add(gdstk.FlexPath([(0,-80),(0,-98)], 4, ends="flush", simple_path=True, layer=6, datatype=0))  # M2
cmp_jpm.add(gdstk.FlexPath([(-2,-73),(-3.81,-73)], 2, ends="flush", simple_path=True, layer=6, datatype=0))  # M2
cmp_jpm.add(gdstk.FlexPath([(-20,0),(-40,0)], 5, ends="flush", simple_path=True, layer=1, datatype=0))  # M1
cmp_jpm.add(gdstk.FlexPath([(-15,-110),(-15,-97.578)], 5, ends="flush", simple_path=True, layer=1, datatype=0))  # M1
cmp_jpm.add(gdstk.FlexPath([(0,-80),(0,-72)], 4, ends="flush", simple_path=True, layer=1, datatype=0))  # M1
cmp_jpm.add(gdstk.FlexPath([(-20,1.5),(-20,-1.5)], 0.5, ends="flush", simple_path=True, layer=63, datatype=0))  # IxTerm
cmp_jpm.add(gdstk.FlexPath([(-1.5,-71),(1.5,-71)], 0.5, ends="flush", simple_path=True, layer=63, datatype=0))  # IxTerm
cmp_jpm.add(gdstk.FlexPath([(-2,97),(2,97)], 0.5, ends="flush", simple_path=True, layer=63, datatype=0))  # IxTerm
cmp_jpm.add(gdstk.Reference(jpmjunction, (-30,0)))
cmp_jpm.add(gdstk.Reference(ejtl2, (-75.25,-88.5)))
cmp_jpm.add(gdstk.Reference(firstordergradiometer, (0,0)))
cmp_jpm.add(gdstk.Reference(jj_103, (-36,-86)))
cmp_jpm.add(gdstk.Reference(jj_104, (-22,-86)))
cmp_jpm.add(gdstk.Reference(jpmbias2, (0,97)))
cmp_jpm.add(gdstk.Reference(jj_102, (-8,-86)))
cmp_jpm.add(gdstk.Reference(jj_105, (8,-86)))
cmp_jpm.add(gdstk.Reference(jj_96, (-7,-75), rotation=3*pi/2))
cmp_jpm.add(gdstk.Reference(via_m2_m1_5, (0,-79)))
cmp_jpm.add(gdstk.Reference(washerinductor, (0,-72)))
cmp_jpm.add(gdstk.Reference(via_m3_m2_3, (0,-73)))
cmp_jpm.add(gdstk.Reference(ejtl2, (46.75,-88.5)))
cmp_jpm.add(gdstk.Label('PL1 M2 M1', (-20,0), layer=64, texttype=0))
cmp_jpm.add(gdstk.Label('PC M3 M1', (0,-71), layer=64, texttype=0))
cmp_jpm.add(gdstk.Label('PB M2 M1', (0,97), layer=64, texttype=0))

lib.write_gds('CMP_JPM.gds')
